VERSION 5.8 ;
BUSBITCHARS "[]" ;
DIVIDERCHAR "/" ;
UNITS
    DATABASE MICRONS 1000 ;
END UNITS

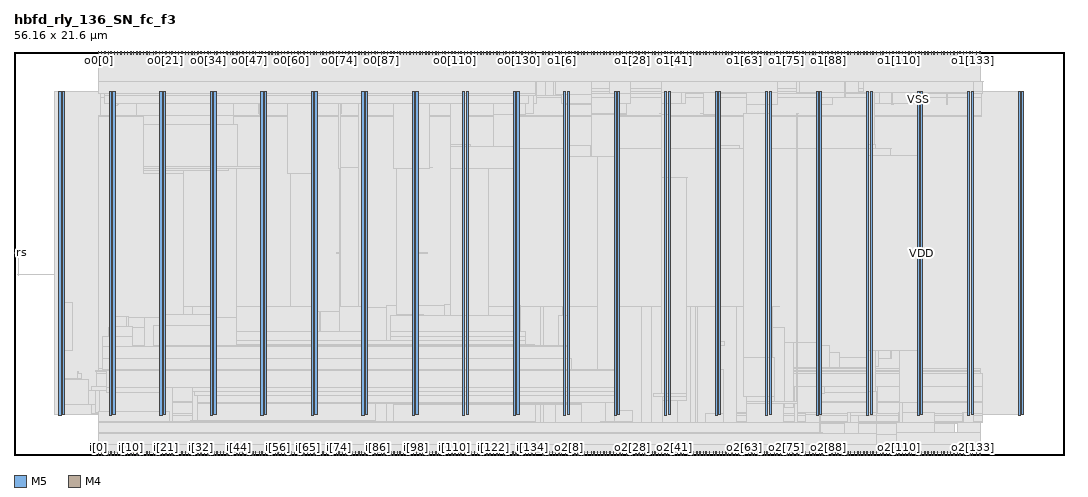
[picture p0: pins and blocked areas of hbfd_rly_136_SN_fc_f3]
MACRO hbfd_rly_136_SN_fc_f3
  FOREIGN hbfd_rly_136_SN_fc_f3 0 0 ;
  CLASS BLOCK ;
  SIZE 56.16 BY 21.6 ;
  PIN clk_in
    DIRECTION INPUT ;
    USE SIGNAL ;
    PORT
      LAYER M5 ;
        RECT  16.176 0 16.2 0.192 ;
    END
  END clk_in
  PIN clk_out0
    DIRECTION OUTPUT ;
    USE SIGNAL ;
    PORT
      LAYER M5 ;
        RECT  16.176 21.408 16.2 21.6 ;
    END
  END clk_out0
  PIN clk_out1
    DIRECTION OUTPUT ;
    USE SIGNAL ;
    PORT
      LAYER M5 ;
        RECT  39.936 21.408 39.96 21.6 ;
    END
  END clk_out1
  PIN clk_out2
    DIRECTION OUTPUT ;
    USE SIGNAL ;
    PORT
      LAYER M5 ;
        RECT  39.936 0 39.96 0.192 ;
    END
  END clk_out2
  PIN i[0]
    DIRECTION INPUT ;
    USE SIGNAL ;
    PORT
      LAYER M5 ;
        RECT  4.512 0 4.536 0.192 ;
    END
  END i[0]
  PIN i[100]
    DIRECTION INPUT ;
    USE SIGNAL ;
    PORT
      LAYER M5 ;
        RECT  21.84 0 21.864 0.192 ;
    END
  END i[100]
  PIN i[101]
    DIRECTION INPUT ;
    USE SIGNAL ;
    PORT
      LAYER M5 ;
        RECT  22.032 0 22.056 0.192 ;
    END
  END i[101]
  PIN i[102]
    DIRECTION INPUT ;
    USE SIGNAL ;
    PORT
      LAYER M5 ;
        RECT  22.176 0 22.2 0.192 ;
    END
  END i[102]
  PIN i[103]
    DIRECTION INPUT ;
    USE SIGNAL ;
    PORT
      LAYER M5 ;
        RECT  22.368 0 22.392 0.192 ;
    END
  END i[103]
  PIN i[104]
    DIRECTION INPUT ;
    USE SIGNAL ;
    PORT
      LAYER M5 ;
        RECT  22.56 0 22.584 0.192 ;
    END
  END i[104]
  PIN i[105]
    DIRECTION INPUT ;
    USE SIGNAL ;
    PORT
      LAYER M5 ;
        RECT  22.704 0 22.728 0.192 ;
    END
  END i[105]
  PIN i[106]
    DIRECTION INPUT ;
    USE SIGNAL ;
    PORT
      LAYER M5 ;
        RECT  22.896 0 22.92 0.192 ;
    END
  END i[106]
  PIN i[107]
    DIRECTION INPUT ;
    USE SIGNAL ;
    PORT
      LAYER M5 ;
        RECT  23.04 0 23.064 0.192 ;
    END
  END i[107]
  PIN i[108]
    DIRECTION INPUT ;
    USE SIGNAL ;
    PORT
      LAYER M5 ;
        RECT  23.232 0 23.256 0.192 ;
    END
  END i[108]
  PIN i[109]
    DIRECTION INPUT ;
    USE SIGNAL ;
    PORT
      LAYER M5 ;
        RECT  23.424 0 23.448 0.192 ;
    END
  END i[109]
  PIN i[10]
    DIRECTION INPUT ;
    USE SIGNAL ;
    PORT
      LAYER M5 ;
        RECT  6.24 0 6.264 0.192 ;
    END
  END i[10]
  PIN i[110]
    DIRECTION INPUT ;
    USE SIGNAL ;
    PORT
      LAYER M5 ;
        RECT  23.568 0 23.592 0.192 ;
    END
  END i[110]
  PIN i[111]
    DIRECTION INPUT ;
    USE SIGNAL ;
    PORT
      LAYER M5 ;
        RECT  23.76 0 23.784 0.192 ;
    END
  END i[111]
  PIN i[112]
    DIRECTION INPUT ;
    USE SIGNAL ;
    PORT
      LAYER M5 ;
        RECT  23.904 0 23.928 0.192 ;
    END
  END i[112]
  PIN i[113]
    DIRECTION INPUT ;
    USE SIGNAL ;
    PORT
      LAYER M5 ;
        RECT  24.096 0 24.12 0.192 ;
    END
  END i[113]
  PIN i[114]
    DIRECTION INPUT ;
    USE SIGNAL ;
    PORT
      LAYER M5 ;
        RECT  24.24 0 24.264 0.192 ;
    END
  END i[114]
  PIN i[115]
    DIRECTION INPUT ;
    USE SIGNAL ;
    PORT
      LAYER M5 ;
        RECT  24.432 0 24.456 0.192 ;
    END
  END i[115]
  PIN i[116]
    DIRECTION INPUT ;
    USE SIGNAL ;
    PORT
      LAYER M5 ;
        RECT  24.624 0 24.648 0.192 ;
    END
  END i[116]
  PIN i[117]
    DIRECTION INPUT ;
    USE SIGNAL ;
    PORT
      LAYER M5 ;
        RECT  24.768 0 24.792 0.192 ;
    END
  END i[117]
  PIN i[118]
    DIRECTION INPUT ;
    USE SIGNAL ;
    PORT
      LAYER M5 ;
        RECT  24.96 0 24.984 0.192 ;
    END
  END i[118]
  PIN i[119]
    DIRECTION INPUT ;
    USE SIGNAL ;
    PORT
      LAYER M5 ;
        RECT  25.104 0 25.128 0.192 ;
    END
  END i[119]
  PIN i[11]
    DIRECTION INPUT ;
    USE SIGNAL ;
    PORT
      LAYER M5 ;
        RECT  6.384 0 6.408 0.192 ;
    END
  END i[11]
  PIN i[120]
    DIRECTION INPUT ;
    USE SIGNAL ;
    PORT
      LAYER M5 ;
        RECT  25.296 0 25.32 0.192 ;
    END
  END i[120]
  PIN i[121]
    DIRECTION INPUT ;
    USE SIGNAL ;
    PORT
      LAYER M5 ;
        RECT  25.44 0 25.464 0.192 ;
    END
  END i[121]
  PIN i[122]
    DIRECTION INPUT ;
    USE SIGNAL ;
    PORT
      LAYER M5 ;
        RECT  25.632 0 25.656 0.192 ;
    END
  END i[122]
  PIN i[123]
    DIRECTION INPUT ;
    USE SIGNAL ;
    PORT
      LAYER M5 ;
        RECT  25.824 0 25.848 0.192 ;
    END
  END i[123]
  PIN i[124]
    DIRECTION INPUT ;
    USE SIGNAL ;
    PORT
      LAYER M5 ;
        RECT  25.968 0 25.992 0.192 ;
    END
  END i[124]
  PIN i[125]
    DIRECTION INPUT ;
    USE SIGNAL ;
    PORT
      LAYER M5 ;
        RECT  26.16 0 26.184 0.192 ;
    END
  END i[125]
  PIN i[126]
    DIRECTION INPUT ;
    USE SIGNAL ;
    PORT
      LAYER M5 ;
        RECT  26.304 0 26.328 0.192 ;
    END
  END i[126]
  PIN i[127]
    DIRECTION INPUT ;
    USE SIGNAL ;
    PORT
      LAYER M5 ;
        RECT  26.496 0 26.52 0.192 ;
    END
  END i[127]
  PIN i[128]
    DIRECTION INPUT ;
    USE SIGNAL ;
    PORT
      LAYER M5 ;
        RECT  26.688 0 26.712 0.192 ;
    END
  END i[128]
  PIN i[129]
    DIRECTION INPUT ;
    USE SIGNAL ;
    PORT
      LAYER M5 ;
        RECT  26.832 0 26.856 0.192 ;
    END
  END i[129]
  PIN i[12]
    DIRECTION INPUT ;
    USE SIGNAL ;
    PORT
      LAYER M5 ;
        RECT  6.576 0 6.6 0.192 ;
    END
  END i[12]
  PIN i[130]
    DIRECTION INPUT ;
    USE SIGNAL ;
    PORT
      LAYER M5 ;
        RECT  27.024 0 27.048 0.192 ;
    END
  END i[130]
  PIN i[131]
    DIRECTION INPUT ;
    USE SIGNAL ;
    PORT
      LAYER M5 ;
        RECT  27.168 0 27.192 0.192 ;
    END
  END i[131]
  PIN i[132]
    DIRECTION INPUT ;
    USE SIGNAL ;
    PORT
      LAYER M5 ;
        RECT  27.36 0 27.384 0.192 ;
    END
  END i[132]
  PIN i[133]
    DIRECTION INPUT ;
    USE SIGNAL ;
    PORT
      LAYER M5 ;
        RECT  27.504 0 27.528 0.192 ;
    END
  END i[133]
  PIN i[134]
    DIRECTION INPUT ;
    USE SIGNAL ;
    PORT
      LAYER M5 ;
        RECT  27.696 0 27.72 0.192 ;
    END
  END i[134]
  PIN i[135]
    DIRECTION INPUT ;
    USE SIGNAL ;
    PORT
      LAYER M5 ;
        RECT  27.888 0 27.912 0.192 ;
    END
  END i[135]
  PIN i[13]
    DIRECTION INPUT ;
    USE SIGNAL ;
    PORT
      LAYER M5 ;
        RECT  6.72 0 6.744 0.192 ;
    END
  END i[13]
  PIN i[14]
    DIRECTION INPUT ;
    USE SIGNAL ;
    PORT
      LAYER M5 ;
        RECT  6.912 0 6.936 0.192 ;
    END
  END i[14]
  PIN i[15]
    DIRECTION INPUT ;
    USE SIGNAL ;
    PORT
      LAYER M5 ;
        RECT  7.104 0 7.128 0.192 ;
    END
  END i[15]
  PIN i[16]
    DIRECTION INPUT ;
    USE SIGNAL ;
    PORT
      LAYER M5 ;
        RECT  7.248 0 7.272 0.192 ;
    END
  END i[16]
  PIN i[17]
    DIRECTION INPUT ;
    USE SIGNAL ;
    PORT
      LAYER M5 ;
        RECT  7.44 0 7.464 0.192 ;
    END
  END i[17]
  PIN i[18]
    DIRECTION INPUT ;
    USE SIGNAL ;
    PORT
      LAYER M5 ;
        RECT  7.584 0 7.608 0.192 ;
    END
  END i[18]
  PIN i[19]
    DIRECTION INPUT ;
    USE SIGNAL ;
    PORT
      LAYER M5 ;
        RECT  7.776 0 7.8 0.192 ;
    END
  END i[19]
  PIN i[1]
    DIRECTION INPUT ;
    USE SIGNAL ;
    PORT
      LAYER M5 ;
        RECT  4.656 0 4.68 0.192 ;
    END
  END i[1]
  PIN i[20]
    DIRECTION INPUT ;
    USE SIGNAL ;
    PORT
      LAYER M5 ;
        RECT  7.92 0 7.944 0.192 ;
    END
  END i[20]
  PIN i[21]
    DIRECTION INPUT ;
    USE SIGNAL ;
    PORT
      LAYER M5 ;
        RECT  8.112 0 8.136 0.192 ;
    END
  END i[21]
  PIN i[22]
    DIRECTION INPUT ;
    USE SIGNAL ;
    PORT
      LAYER M5 ;
        RECT  8.304 0 8.328 0.192 ;
    END
  END i[22]
  PIN i[23]
    DIRECTION INPUT ;
    USE SIGNAL ;
    PORT
      LAYER M5 ;
        RECT  8.448 0 8.472 0.192 ;
    END
  END i[23]
  PIN i[24]
    DIRECTION INPUT ;
    USE SIGNAL ;
    PORT
      LAYER M5 ;
        RECT  8.64 0 8.664 0.192 ;
    END
  END i[24]
  PIN i[25]
    DIRECTION INPUT ;
    USE SIGNAL ;
    PORT
      LAYER M5 ;
        RECT  8.784 0 8.808 0.192 ;
    END
  END i[25]
  PIN i[26]
    DIRECTION INPUT ;
    USE SIGNAL ;
    PORT
      LAYER M5 ;
        RECT  8.976 0 9 0.192 ;
    END
  END i[26]
  PIN i[27]
    DIRECTION INPUT ;
    USE SIGNAL ;
    PORT
      LAYER M5 ;
        RECT  9.168 0 9.192 0.192 ;
    END
  END i[27]
  PIN i[28]
    DIRECTION INPUT ;
    USE SIGNAL ;
    PORT
      LAYER M5 ;
        RECT  9.312 0 9.336 0.192 ;
    END
  END i[28]
  PIN i[29]
    DIRECTION INPUT ;
    USE SIGNAL ;
    PORT
      LAYER M5 ;
        RECT  9.504 0 9.528 0.192 ;
    END
  END i[29]
  PIN i[2]
    DIRECTION INPUT ;
    USE SIGNAL ;
    PORT
      LAYER M5 ;
        RECT  4.848 0 4.872 0.192 ;
    END
  END i[2]
  PIN i[30]
    DIRECTION INPUT ;
    USE SIGNAL ;
    PORT
      LAYER M5 ;
        RECT  9.648 0 9.672 0.192 ;
    END
  END i[30]
  PIN i[31]
    DIRECTION INPUT ;
    USE SIGNAL ;
    PORT
      LAYER M5 ;
        RECT  9.84 0 9.864 0.192 ;
    END
  END i[31]
  PIN i[32]
    DIRECTION INPUT ;
    USE SIGNAL ;
    PORT
      LAYER M5 ;
        RECT  9.984 0 10.008 0.192 ;
    END
  END i[32]
  PIN i[33]
    DIRECTION INPUT ;
    USE SIGNAL ;
    PORT
      LAYER M5 ;
        RECT  10.176 0 10.2 0.192 ;
    END
  END i[33]
  PIN i[34]
    DIRECTION INPUT ;
    USE SIGNAL ;
    PORT
      LAYER M5 ;
        RECT  10.368 0 10.392 0.192 ;
    END
  END i[34]
  PIN i[35]
    DIRECTION INPUT ;
    USE SIGNAL ;
    PORT
      LAYER M5 ;
        RECT  10.512 0 10.536 0.192 ;
    END
  END i[35]
  PIN i[36]
    DIRECTION INPUT ;
    USE SIGNAL ;
    PORT
      LAYER M5 ;
        RECT  10.704 0 10.728 0.192 ;
    END
  END i[36]
  PIN i[37]
    DIRECTION INPUT ;
    USE SIGNAL ;
    PORT
      LAYER M5 ;
        RECT  10.848 0 10.872 0.192 ;
    END
  END i[37]
  PIN i[38]
    DIRECTION INPUT ;
    USE SIGNAL ;
    PORT
      LAYER M5 ;
        RECT  11.04 0 11.064 0.192 ;
    END
  END i[38]
  PIN i[39]
    DIRECTION INPUT ;
    USE SIGNAL ;
    PORT
      LAYER M5 ;
        RECT  11.184 0 11.208 0.192 ;
    END
  END i[39]
  PIN i[3]
    DIRECTION INPUT ;
    USE SIGNAL ;
    PORT
      LAYER M5 ;
        RECT  5.04 0 5.064 0.192 ;
    END
  END i[3]
  PIN i[40]
    DIRECTION INPUT ;
    USE SIGNAL ;
    PORT
      LAYER M5 ;
        RECT  11.376 0 11.4 0.192 ;
    END
  END i[40]
  PIN i[41]
    DIRECTION INPUT ;
    USE SIGNAL ;
    PORT
      LAYER M5 ;
        RECT  11.568 0 11.592 0.192 ;
    END
  END i[41]
  PIN i[42]
    DIRECTION INPUT ;
    USE SIGNAL ;
    PORT
      LAYER M5 ;
        RECT  11.712 0 11.736 0.192 ;
    END
  END i[42]
  PIN i[43]
    DIRECTION INPUT ;
    USE SIGNAL ;
    PORT
      LAYER M5 ;
        RECT  11.904 0 11.928 0.192 ;
    END
  END i[43]
  PIN i[44]
    DIRECTION INPUT ;
    USE SIGNAL ;
    PORT
      LAYER M5 ;
        RECT  12.048 0 12.072 0.192 ;
    END
  END i[44]
  PIN i[45]
    DIRECTION INPUT ;
    USE SIGNAL ;
    PORT
      LAYER M5 ;
        RECT  12.24 0 12.264 0.192 ;
    END
  END i[45]
  PIN i[46]
    DIRECTION INPUT ;
    USE SIGNAL ;
    PORT
      LAYER M5 ;
        RECT  12.432 0 12.456 0.192 ;
    END
  END i[46]
  PIN i[47]
    DIRECTION INPUT ;
    USE SIGNAL ;
    PORT
      LAYER M5 ;
        RECT  12.576 0 12.6 0.192 ;
    END
  END i[47]
  PIN i[48]
    DIRECTION INPUT ;
    USE SIGNAL ;
    PORT
      LAYER M5 ;
        RECT  12.768 0 12.792 0.192 ;
    END
  END i[48]
  PIN i[49]
    DIRECTION INPUT ;
    USE SIGNAL ;
    PORT
      LAYER M5 ;
        RECT  12.912 0 12.936 0.192 ;
    END
  END i[49]
  PIN i[4]
    DIRECTION INPUT ;
    USE SIGNAL ;
    PORT
      LAYER M5 ;
        RECT  5.184 0 5.208 0.192 ;
    END
  END i[4]
  PIN i[50]
    DIRECTION INPUT ;
    USE SIGNAL ;
    PORT
      LAYER M5 ;
        RECT  13.104 0 13.128 0.192 ;
    END
  END i[50]
  PIN i[51]
    DIRECTION INPUT ;
    USE SIGNAL ;
    PORT
      LAYER M5 ;
        RECT  13.248 0 13.272 0.192 ;
    END
  END i[51]
  PIN i[52]
    DIRECTION INPUT ;
    USE SIGNAL ;
    PORT
      LAYER M5 ;
        RECT  13.44 0 13.464 0.192 ;
    END
  END i[52]
  PIN i[53]
    DIRECTION INPUT ;
    USE SIGNAL ;
    PORT
      LAYER M5 ;
        RECT  13.632 0 13.656 0.192 ;
    END
  END i[53]
  PIN i[54]
    DIRECTION INPUT ;
    USE SIGNAL ;
    PORT
      LAYER M5 ;
        RECT  13.776 0 13.8 0.192 ;
    END
  END i[54]
  PIN i[55]
    DIRECTION INPUT ;
    USE SIGNAL ;
    PORT
      LAYER M5 ;
        RECT  13.968 0 13.992 0.192 ;
    END
  END i[55]
  PIN i[56]
    DIRECTION INPUT ;
    USE SIGNAL ;
    PORT
      LAYER M5 ;
        RECT  14.112 0 14.136 0.192 ;
    END
  END i[56]
  PIN i[57]
    DIRECTION INPUT ;
    USE SIGNAL ;
    PORT
      LAYER M5 ;
        RECT  14.304 0 14.328 0.192 ;
    END
  END i[57]
  PIN i[58]
    DIRECTION INPUT ;
    USE SIGNAL ;
    PORT
      LAYER M5 ;
        RECT  14.448 0 14.472 0.192 ;
    END
  END i[58]
  PIN i[59]
    DIRECTION INPUT ;
    USE SIGNAL ;
    PORT
      LAYER M5 ;
        RECT  14.64 0 14.664 0.192 ;
    END
  END i[59]
  PIN i[5]
    DIRECTION INPUT ;
    USE SIGNAL ;
    PORT
      LAYER M5 ;
        RECT  5.376 0 5.4 0.192 ;
    END
  END i[5]
  PIN i[60]
    DIRECTION INPUT ;
    USE SIGNAL ;
    PORT
      LAYER M5 ;
        RECT  14.832 0 14.856 0.192 ;
    END
  END i[60]
  PIN i[61]
    DIRECTION INPUT ;
    USE SIGNAL ;
    PORT
      LAYER M5 ;
        RECT  14.976 0 15 0.192 ;
    END
  END i[61]
  PIN i[62]
    DIRECTION INPUT ;
    USE SIGNAL ;
    PORT
      LAYER M5 ;
        RECT  15.168 0 15.192 0.192 ;
    END
  END i[62]
  PIN i[63]
    DIRECTION INPUT ;
    USE SIGNAL ;
    PORT
      LAYER M5 ;
        RECT  15.312 0 15.336 0.192 ;
    END
  END i[63]
  PIN i[64]
    DIRECTION INPUT ;
    USE SIGNAL ;
    PORT
      LAYER M5 ;
        RECT  15.504 0 15.528 0.192 ;
    END
  END i[64]
  PIN i[65]
    DIRECTION INPUT ;
    USE SIGNAL ;
    PORT
      LAYER M5 ;
        RECT  15.696 0 15.72 0.192 ;
    END
  END i[65]
  PIN i[66]
    DIRECTION INPUT ;
    USE SIGNAL ;
    PORT
      LAYER M5 ;
        RECT  15.84 0 15.864 0.192 ;
    END
  END i[66]
  PIN i[67]
    DIRECTION INPUT ;
    USE SIGNAL ;
    PORT
      LAYER M5 ;
        RECT  16.032 0 16.056 0.192 ;
    END
  END i[67]
  PIN i[68]
    DIRECTION INPUT ;
    USE SIGNAL ;
    PORT
      LAYER M5 ;
        RECT  16.368 0 16.392 0.192 ;
    END
  END i[68]
  PIN i[69]
    DIRECTION INPUT ;
    USE SIGNAL ;
    PORT
      LAYER M5 ;
        RECT  16.512 0 16.536 0.192 ;
    END
  END i[69]
  PIN i[6]
    DIRECTION INPUT ;
    USE SIGNAL ;
    PORT
      LAYER M5 ;
        RECT  5.52 0 5.544 0.192 ;
    END
  END i[6]
  PIN i[70]
    DIRECTION INPUT ;
    USE SIGNAL ;
    PORT
      LAYER M5 ;
        RECT  16.704 0 16.728 0.192 ;
    END
  END i[70]
  PIN i[71]
    DIRECTION INPUT ;
    USE SIGNAL ;
    PORT
      LAYER M5 ;
        RECT  16.896 0 16.92 0.192 ;
    END
  END i[71]
  PIN i[72]
    DIRECTION INPUT ;
    USE SIGNAL ;
    PORT
      LAYER M5 ;
        RECT  17.04 0 17.064 0.192 ;
    END
  END i[72]
  PIN i[73]
    DIRECTION INPUT ;
    USE SIGNAL ;
    PORT
      LAYER M5 ;
        RECT  17.232 0 17.256 0.192 ;
    END
  END i[73]
  PIN i[74]
    DIRECTION INPUT ;
    USE SIGNAL ;
    PORT
      LAYER M5 ;
        RECT  17.376 0 17.4 0.192 ;
    END
  END i[74]
  PIN i[75]
    DIRECTION INPUT ;
    USE SIGNAL ;
    PORT
      LAYER M5 ;
        RECT  17.568 0 17.592 0.192 ;
    END
  END i[75]
  PIN i[76]
    DIRECTION INPUT ;
    USE SIGNAL ;
    PORT
      LAYER M5 ;
        RECT  17.712 0 17.736 0.192 ;
    END
  END i[76]
  PIN i[77]
    DIRECTION INPUT ;
    USE SIGNAL ;
    PORT
      LAYER M5 ;
        RECT  17.904 0 17.928 0.192 ;
    END
  END i[77]
  PIN i[78]
    DIRECTION INPUT ;
    USE SIGNAL ;
    PORT
      LAYER M5 ;
        RECT  18.096 0 18.12 0.192 ;
    END
  END i[78]
  PIN i[79]
    DIRECTION INPUT ;
    USE SIGNAL ;
    PORT
      LAYER M5 ;
        RECT  18.24 0 18.264 0.192 ;
    END
  END i[79]
  PIN i[7]
    DIRECTION INPUT ;
    USE SIGNAL ;
    PORT
      LAYER M5 ;
        RECT  5.712 0 5.736 0.192 ;
    END
  END i[7]
  PIN i[80]
    DIRECTION INPUT ;
    USE SIGNAL ;
    PORT
      LAYER M5 ;
        RECT  18.432 0 18.456 0.192 ;
    END
  END i[80]
  PIN i[81]
    DIRECTION INPUT ;
    USE SIGNAL ;
    PORT
      LAYER M5 ;
        RECT  18.576 0 18.6 0.192 ;
    END
  END i[81]
  PIN i[82]
    DIRECTION INPUT ;
    USE SIGNAL ;
    PORT
      LAYER M5 ;
        RECT  18.768 0 18.792 0.192 ;
    END
  END i[82]
  PIN i[83]
    DIRECTION INPUT ;
    USE SIGNAL ;
    PORT
      LAYER M5 ;
        RECT  18.96 0 18.984 0.192 ;
    END
  END i[83]
  PIN i[84]
    DIRECTION INPUT ;
    USE SIGNAL ;
    PORT
      LAYER M5 ;
        RECT  19.104 0 19.128 0.192 ;
    END
  END i[84]
  PIN i[85]
    DIRECTION INPUT ;
    USE SIGNAL ;
    PORT
      LAYER M5 ;
        RECT  19.296 0 19.32 0.192 ;
    END
  END i[85]
  PIN i[86]
    DIRECTION INPUT ;
    USE SIGNAL ;
    PORT
      LAYER M5 ;
        RECT  19.44 0 19.464 0.192 ;
    END
  END i[86]
  PIN i[87]
    DIRECTION INPUT ;
    USE SIGNAL ;
    PORT
      LAYER M5 ;
        RECT  19.632 0 19.656 0.192 ;
    END
  END i[87]
  PIN i[88]
    DIRECTION INPUT ;
    USE SIGNAL ;
    PORT
      LAYER M5 ;
        RECT  19.776 0 19.8 0.192 ;
    END
  END i[88]
  PIN i[89]
    DIRECTION INPUT ;
    USE SIGNAL ;
    PORT
      LAYER M5 ;
        RECT  19.968 0 19.992 0.192 ;
    END
  END i[89]
  PIN i[8]
    DIRECTION INPUT ;
    USE SIGNAL ;
    PORT
      LAYER M5 ;
        RECT  5.904 0 5.928 0.192 ;
    END
  END i[8]
  PIN i[90]
    DIRECTION INPUT ;
    USE SIGNAL ;
    PORT
      LAYER M5 ;
        RECT  20.16 0 20.184 0.192 ;
    END
  END i[90]
  PIN i[91]
    DIRECTION INPUT ;
    USE SIGNAL ;
    PORT
      LAYER M5 ;
        RECT  20.304 0 20.328 0.192 ;
    END
  END i[91]
  PIN i[92]
    DIRECTION INPUT ;
    USE SIGNAL ;
    PORT
      LAYER M5 ;
        RECT  20.496 0 20.52 0.192 ;
    END
  END i[92]
  PIN i[93]
    DIRECTION INPUT ;
    USE SIGNAL ;
    PORT
      LAYER M5 ;
        RECT  20.64 0 20.664 0.192 ;
    END
  END i[93]
  PIN i[94]
    DIRECTION INPUT ;
    USE SIGNAL ;
    PORT
      LAYER M5 ;
        RECT  20.832 0 20.856 0.192 ;
    END
  END i[94]
  PIN i[95]
    DIRECTION INPUT ;
    USE SIGNAL ;
    PORT
      LAYER M5 ;
        RECT  20.976 0 21 0.192 ;
    END
  END i[95]
  PIN i[96]
    DIRECTION INPUT ;
    USE SIGNAL ;
    PORT
      LAYER M5 ;
        RECT  21.168 0 21.192 0.192 ;
    END
  END i[96]
  PIN i[97]
    DIRECTION INPUT ;
    USE SIGNAL ;
    PORT
      LAYER M5 ;
        RECT  21.36 0 21.384 0.192 ;
    END
  END i[97]
  PIN i[98]
    DIRECTION INPUT ;
    USE SIGNAL ;
    PORT
      LAYER M5 ;
        RECT  21.504 0 21.528 0.192 ;
    END
  END i[98]
  PIN i[99]
    DIRECTION INPUT ;
    USE SIGNAL ;
    PORT
      LAYER M5 ;
        RECT  21.696 0 21.72 0.192 ;
    END
  END i[99]
  PIN i[9]
    DIRECTION INPUT ;
    USE SIGNAL ;
    PORT
      LAYER M5 ;
        RECT  6.048 0 6.072 0.192 ;
    END
  END i[9]
  PIN o0[0]
    DIRECTION OUTPUT ;
    USE SIGNAL ;
    PORT
      LAYER M5 ;
        RECT  4.512 21.408 4.536 21.6 ;
    END
  END o0[0]
  PIN o0[100]
    DIRECTION OUTPUT ;
    USE SIGNAL ;
    PORT
      LAYER M5 ;
        RECT  21.84 21.408 21.864 21.6 ;
    END
  END o0[100]
  PIN o0[101]
    DIRECTION OUTPUT ;
    USE SIGNAL ;
    PORT
      LAYER M5 ;
        RECT  22.032 21.408 22.056 21.6 ;
    END
  END o0[101]
  PIN o0[102]
    DIRECTION OUTPUT ;
    USE SIGNAL ;
    PORT
      LAYER M5 ;
        RECT  22.176 21.408 22.2 21.6 ;
    END
  END o0[102]
  PIN o0[103]
    DIRECTION OUTPUT ;
    USE SIGNAL ;
    PORT
      LAYER M5 ;
        RECT  22.368 21.408 22.392 21.6 ;
    END
  END o0[103]
  PIN o0[104]
    DIRECTION OUTPUT ;
    USE SIGNAL ;
    PORT
      LAYER M5 ;
        RECT  22.56 21.408 22.584 21.6 ;
    END
  END o0[104]
  PIN o0[105]
    DIRECTION OUTPUT ;
    USE SIGNAL ;
    PORT
      LAYER M5 ;
        RECT  22.704 21.408 22.728 21.6 ;
    END
  END o0[105]
  PIN o0[106]
    DIRECTION OUTPUT ;
    USE SIGNAL ;
    PORT
      LAYER M5 ;
        RECT  22.896 21.408 22.92 21.6 ;
    END
  END o0[106]
  PIN o0[107]
    DIRECTION OUTPUT ;
    USE SIGNAL ;
    PORT
      LAYER M5 ;
        RECT  23.04 21.408 23.064 21.6 ;
    END
  END o0[107]
  PIN o0[108]
    DIRECTION OUTPUT ;
    USE SIGNAL ;
    PORT
      LAYER M5 ;
        RECT  23.232 21.408 23.256 21.6 ;
    END
  END o0[108]
  PIN o0[109]
    DIRECTION OUTPUT ;
    USE SIGNAL ;
    PORT
      LAYER M5 ;
        RECT  23.424 21.408 23.448 21.6 ;
    END
  END o0[109]
  PIN o0[10]
    DIRECTION OUTPUT ;
    USE SIGNAL ;
    PORT
      LAYER M5 ;
        RECT  6.24 21.408 6.264 21.6 ;
    END
  END o0[10]
  PIN o0[110]
    DIRECTION OUTPUT ;
    USE SIGNAL ;
    PORT
      LAYER M5 ;
        RECT  23.568 21.408 23.592 21.6 ;
    END
  END o0[110]
  PIN o0[111]
    DIRECTION OUTPUT ;
    USE SIGNAL ;
    PORT
      LAYER M5 ;
        RECT  23.76 21.408 23.784 21.6 ;
    END
  END o0[111]
  PIN o0[112]
    DIRECTION OUTPUT ;
    USE SIGNAL ;
    PORT
      LAYER M5 ;
        RECT  23.904 21.408 23.928 21.6 ;
    END
  END o0[112]
  PIN o0[113]
    DIRECTION OUTPUT ;
    USE SIGNAL ;
    PORT
      LAYER M5 ;
        RECT  24.096 21.408 24.12 21.6 ;
    END
  END o0[113]
  PIN o0[114]
    DIRECTION OUTPUT ;
    USE SIGNAL ;
    PORT
      LAYER M5 ;
        RECT  24.24 21.408 24.264 21.6 ;
    END
  END o0[114]
  PIN o0[115]
    DIRECTION OUTPUT ;
    USE SIGNAL ;
    PORT
      LAYER M5 ;
        RECT  24.432 21.408 24.456 21.6 ;
    END
  END o0[115]
  PIN o0[116]
    DIRECTION OUTPUT ;
    USE SIGNAL ;
    PORT
      LAYER M5 ;
        RECT  24.624 21.408 24.648 21.6 ;
    END
  END o0[116]
  PIN o0[117]
    DIRECTION OUTPUT ;
    USE SIGNAL ;
    PORT
      LAYER M5 ;
        RECT  24.768 21.408 24.792 21.6 ;
    END
  END o0[117]
  PIN o0[118]
    DIRECTION OUTPUT ;
    USE SIGNAL ;
    PORT
      LAYER M5 ;
        RECT  24.96 21.408 24.984 21.6 ;
    END
  END o0[118]
  PIN o0[119]
    DIRECTION OUTPUT ;
    USE SIGNAL ;
    PORT
      LAYER M5 ;
        RECT  25.104 21.408 25.128 21.6 ;
    END
  END o0[119]
  PIN o0[11]
    DIRECTION OUTPUT ;
    USE SIGNAL ;
    PORT
      LAYER M5 ;
        RECT  6.384 21.408 6.408 21.6 ;
    END
  END o0[11]
  PIN o0[120]
    DIRECTION OUTPUT ;
    USE SIGNAL ;
    PORT
      LAYER M5 ;
        RECT  25.296 21.408 25.32 21.6 ;
    END
  END o0[120]
  PIN o0[121]
    DIRECTION OUTPUT ;
    USE SIGNAL ;
    PORT
      LAYER M5 ;
        RECT  25.44 21.408 25.464 21.6 ;
    END
  END o0[121]
  PIN o0[122]
    DIRECTION OUTPUT ;
    USE SIGNAL ;
    PORT
      LAYER M5 ;
        RECT  25.632 21.408 25.656 21.6 ;
    END
  END o0[122]
  PIN o0[123]
    DIRECTION OUTPUT ;
    USE SIGNAL ;
    PORT
      LAYER M5 ;
        RECT  25.824 21.408 25.848 21.6 ;
    END
  END o0[123]
  PIN o0[124]
    DIRECTION OUTPUT ;
    USE SIGNAL ;
    PORT
      LAYER M5 ;
        RECT  25.968 21.408 25.992 21.6 ;
    END
  END o0[124]
  PIN o0[125]
    DIRECTION OUTPUT ;
    USE SIGNAL ;
    PORT
      LAYER M5 ;
        RECT  26.16 21.408 26.184 21.6 ;
    END
  END o0[125]
  PIN o0[126]
    DIRECTION OUTPUT ;
    USE SIGNAL ;
    PORT
      LAYER M5 ;
        RECT  26.304 21.408 26.328 21.6 ;
    END
  END o0[126]
  PIN o0[127]
    DIRECTION OUTPUT ;
    USE SIGNAL ;
    PORT
      LAYER M5 ;
        RECT  26.496 21.408 26.52 21.6 ;
    END
  END o0[127]
  PIN o0[128]
    DIRECTION OUTPUT ;
    USE SIGNAL ;
    PORT
      LAYER M5 ;
        RECT  26.688 21.408 26.712 21.6 ;
    END
  END o0[128]
  PIN o0[129]
    DIRECTION OUTPUT ;
    USE SIGNAL ;
    PORT
      LAYER M5 ;
        RECT  26.832 21.408 26.856 21.6 ;
    END
  END o0[129]
  PIN o0[12]
    DIRECTION OUTPUT ;
    USE SIGNAL ;
    PORT
      LAYER M5 ;
        RECT  6.576 21.408 6.6 21.6 ;
    END
  END o0[12]
  PIN o0[130]
    DIRECTION OUTPUT ;
    USE SIGNAL ;
    PORT
      LAYER M5 ;
        RECT  27.024 21.408 27.048 21.6 ;
    END
  END o0[130]
  PIN o0[131]
    DIRECTION OUTPUT ;
    USE SIGNAL ;
    PORT
      LAYER M5 ;
        RECT  27.168 21.408 27.192 21.6 ;
    END
  END o0[131]
  PIN o0[132]
    DIRECTION OUTPUT ;
    USE SIGNAL ;
    PORT
      LAYER M5 ;
        RECT  27.36 21.408 27.384 21.6 ;
    END
  END o0[132]
  PIN o0[133]
    DIRECTION OUTPUT ;
    USE SIGNAL ;
    PORT
      LAYER M5 ;
        RECT  27.504 21.408 27.528 21.6 ;
    END
  END o0[133]
  PIN o0[134]
    DIRECTION OUTPUT ;
    USE SIGNAL ;
    PORT
      LAYER M5 ;
        RECT  27.696 21.408 27.72 21.6 ;
    END
  END o0[134]
  PIN o0[135]
    DIRECTION OUTPUT ;
    USE SIGNAL ;
    PORT
      LAYER M5 ;
        RECT  27.888 21.408 27.912 21.6 ;
    END
  END o0[135]
  PIN o0[13]
    DIRECTION OUTPUT ;
    USE SIGNAL ;
    PORT
      LAYER M5 ;
        RECT  6.72 21.408 6.744 21.6 ;
    END
  END o0[13]
  PIN o0[14]
    DIRECTION OUTPUT ;
    USE SIGNAL ;
    PORT
      LAYER M5 ;
        RECT  6.912 21.408 6.936 21.6 ;
    END
  END o0[14]
  PIN o0[15]
    DIRECTION OUTPUT ;
    USE SIGNAL ;
    PORT
      LAYER M5 ;
        RECT  7.104 21.408 7.128 21.6 ;
    END
  END o0[15]
  PIN o0[16]
    DIRECTION OUTPUT ;
    USE SIGNAL ;
    PORT
      LAYER M5 ;
        RECT  7.248 21.408 7.272 21.6 ;
    END
  END o0[16]
  PIN o0[17]
    DIRECTION OUTPUT ;
    USE SIGNAL ;
    PORT
      LAYER M5 ;
        RECT  7.44 21.408 7.464 21.6 ;
    END
  END o0[17]
  PIN o0[18]
    DIRECTION OUTPUT ;
    USE SIGNAL ;
    PORT
      LAYER M5 ;
        RECT  7.584 21.408 7.608 21.6 ;
    END
  END o0[18]
  PIN o0[19]
    DIRECTION OUTPUT ;
    USE SIGNAL ;
    PORT
      LAYER M5 ;
        RECT  7.776 21.408 7.8 21.6 ;
    END
  END o0[19]
  PIN o0[1]
    DIRECTION OUTPUT ;
    USE SIGNAL ;
    PORT
      LAYER M5 ;
        RECT  4.656 21.408 4.68 21.6 ;
    END
  END o0[1]
  PIN o0[20]
    DIRECTION OUTPUT ;
    USE SIGNAL ;
    PORT
      LAYER M5 ;
        RECT  7.92 21.408 7.944 21.6 ;
    END
  END o0[20]
  PIN o0[21]
    DIRECTION OUTPUT ;
    USE SIGNAL ;
    PORT
      LAYER M5 ;
        RECT  8.112 21.408 8.136 21.6 ;
    END
  END o0[21]
  PIN o0[22]
    DIRECTION OUTPUT ;
    USE SIGNAL ;
    PORT
      LAYER M5 ;
        RECT  8.304 21.408 8.328 21.6 ;
    END
  END o0[22]
  PIN o0[23]
    DIRECTION OUTPUT ;
    USE SIGNAL ;
    PORT
      LAYER M5 ;
        RECT  8.448 21.408 8.472 21.6 ;
    END
  END o0[23]
  PIN o0[24]
    DIRECTION OUTPUT ;
    USE SIGNAL ;
    PORT
      LAYER M5 ;
        RECT  8.64 21.408 8.664 21.6 ;
    END
  END o0[24]
  PIN o0[25]
    DIRECTION OUTPUT ;
    USE SIGNAL ;
    PORT
      LAYER M5 ;
        RECT  8.784 21.408 8.808 21.6 ;
    END
  END o0[25]
  PIN o0[26]
    DIRECTION OUTPUT ;
    USE SIGNAL ;
    PORT
      LAYER M5 ;
        RECT  8.976 21.408 9 21.6 ;
    END
  END o0[26]
  PIN o0[27]
    DIRECTION OUTPUT ;
    USE SIGNAL ;
    PORT
      LAYER M5 ;
        RECT  9.168 21.408 9.192 21.6 ;
    END
  END o0[27]
  PIN o0[28]
    DIRECTION OUTPUT ;
    USE SIGNAL ;
    PORT
      LAYER M5 ;
        RECT  9.312 21.408 9.336 21.6 ;
    END
  END o0[28]
  PIN o0[29]
    DIRECTION OUTPUT ;
    USE SIGNAL ;
    PORT
      LAYER M5 ;
        RECT  9.504 21.408 9.528 21.6 ;
    END
  END o0[29]
  PIN o0[2]
    DIRECTION OUTPUT ;
    USE SIGNAL ;
    PORT
      LAYER M5 ;
        RECT  4.848 21.408 4.872 21.6 ;
    END
  END o0[2]
  PIN o0[30]
    DIRECTION OUTPUT ;
    USE SIGNAL ;
    PORT
      LAYER M5 ;
        RECT  9.648 21.408 9.672 21.6 ;
    END
  END o0[30]
  PIN o0[31]
    DIRECTION OUTPUT ;
    USE SIGNAL ;
    PORT
      LAYER M5 ;
        RECT  9.84 21.408 9.864 21.6 ;
    END
  END o0[31]
  PIN o0[32]
    DIRECTION OUTPUT ;
    USE SIGNAL ;
    PORT
      LAYER M5 ;
        RECT  9.984 21.408 10.008 21.6 ;
    END
  END o0[32]
  PIN o0[33]
    DIRECTION OUTPUT ;
    USE SIGNAL ;
    PORT
      LAYER M5 ;
        RECT  10.176 21.408 10.2 21.6 ;
    END
  END o0[33]
  PIN o0[34]
    DIRECTION OUTPUT ;
    USE SIGNAL ;
    PORT
      LAYER M5 ;
        RECT  10.368 21.408 10.392 21.6 ;
    END
  END o0[34]
  PIN o0[35]
    DIRECTION OUTPUT ;
    USE SIGNAL ;
    PORT
      LAYER M5 ;
        RECT  10.512 21.408 10.536 21.6 ;
    END
  END o0[35]
  PIN o0[36]
    DIRECTION OUTPUT ;
    USE SIGNAL ;
    PORT
      LAYER M5 ;
        RECT  10.704 21.408 10.728 21.6 ;
    END
  END o0[36]
  PIN o0[37]
    DIRECTION OUTPUT ;
    USE SIGNAL ;
    PORT
      LAYER M5 ;
        RECT  10.848 21.408 10.872 21.6 ;
    END
  END o0[37]
  PIN o0[38]
    DIRECTION OUTPUT ;
    USE SIGNAL ;
    PORT
      LAYER M5 ;
        RECT  11.04 21.408 11.064 21.6 ;
    END
  END o0[38]
  PIN o0[39]
    DIRECTION OUTPUT ;
    USE SIGNAL ;
    PORT
      LAYER M5 ;
        RECT  11.184 21.408 11.208 21.6 ;
    END
  END o0[39]
  PIN o0[3]
    DIRECTION OUTPUT ;
    USE SIGNAL ;
    PORT
      LAYER M5 ;
        RECT  5.04 21.408 5.064 21.6 ;
    END
  END o0[3]
  PIN o0[40]
    DIRECTION OUTPUT ;
    USE SIGNAL ;
    PORT
      LAYER M5 ;
        RECT  11.376 21.408 11.4 21.6 ;
    END
  END o0[40]
  PIN o0[41]
    DIRECTION OUTPUT ;
    USE SIGNAL ;
    PORT
      LAYER M5 ;
        RECT  11.568 21.408 11.592 21.6 ;
    END
  END o0[41]
  PIN o0[42]
    DIRECTION OUTPUT ;
    USE SIGNAL ;
    PORT
      LAYER M5 ;
        RECT  11.712 21.408 11.736 21.6 ;
    END
  END o0[42]
  PIN o0[43]
    DIRECTION OUTPUT ;
    USE SIGNAL ;
    PORT
      LAYER M5 ;
        RECT  11.904 21.408 11.928 21.6 ;
    END
  END o0[43]
  PIN o0[44]
    DIRECTION OUTPUT ;
    USE SIGNAL ;
    PORT
      LAYER M5 ;
        RECT  12.048 21.408 12.072 21.6 ;
    END
  END o0[44]
  PIN o0[45]
    DIRECTION OUTPUT ;
    USE SIGNAL ;
    PORT
      LAYER M5 ;
        RECT  12.24 21.408 12.264 21.6 ;
    END
  END o0[45]
  PIN o0[46]
    DIRECTION OUTPUT ;
    USE SIGNAL ;
    PORT
      LAYER M5 ;
        RECT  12.432 21.408 12.456 21.6 ;
    END
  END o0[46]
  PIN o0[47]
    DIRECTION OUTPUT ;
    USE SIGNAL ;
    PORT
      LAYER M5 ;
        RECT  12.576 21.408 12.6 21.6 ;
    END
  END o0[47]
  PIN o0[48]
    DIRECTION OUTPUT ;
    USE SIGNAL ;
    PORT
      LAYER M5 ;
        RECT  12.768 21.408 12.792 21.6 ;
    END
  END o0[48]
  PIN o0[49]
    DIRECTION OUTPUT ;
    USE SIGNAL ;
    PORT
      LAYER M5 ;
        RECT  12.912 21.408 12.936 21.6 ;
    END
  END o0[49]
  PIN o0[4]
    DIRECTION OUTPUT ;
    USE SIGNAL ;
    PORT
      LAYER M5 ;
        RECT  5.184 21.408 5.208 21.6 ;
    END
  END o0[4]
  PIN o0[50]
    DIRECTION OUTPUT ;
    USE SIGNAL ;
    PORT
      LAYER M5 ;
        RECT  13.104 21.408 13.128 21.6 ;
    END
  END o0[50]
  PIN o0[51]
    DIRECTION OUTPUT ;
    USE SIGNAL ;
    PORT
      LAYER M5 ;
        RECT  13.248 21.408 13.272 21.6 ;
    END
  END o0[51]
  PIN o0[52]
    DIRECTION OUTPUT ;
    USE SIGNAL ;
    PORT
      LAYER M5 ;
        RECT  13.44 21.408 13.464 21.6 ;
    END
  END o0[52]
  PIN o0[53]
    DIRECTION OUTPUT ;
    USE SIGNAL ;
    PORT
      LAYER M5 ;
        RECT  13.632 21.408 13.656 21.6 ;
    END
  END o0[53]
  PIN o0[54]
    DIRECTION OUTPUT ;
    USE SIGNAL ;
    PORT
      LAYER M5 ;
        RECT  13.776 21.408 13.8 21.6 ;
    END
  END o0[54]
  PIN o0[55]
    DIRECTION OUTPUT ;
    USE SIGNAL ;
    PORT
      LAYER M5 ;
        RECT  13.968 21.408 13.992 21.6 ;
    END
  END o0[55]
  PIN o0[56]
    DIRECTION OUTPUT ;
    USE SIGNAL ;
    PORT
      LAYER M5 ;
        RECT  14.112 21.408 14.136 21.6 ;
    END
  END o0[56]
  PIN o0[57]
    DIRECTION OUTPUT ;
    USE SIGNAL ;
    PORT
      LAYER M5 ;
        RECT  14.304 21.408 14.328 21.6 ;
    END
  END o0[57]
  PIN o0[58]
    DIRECTION OUTPUT ;
    USE SIGNAL ;
    PORT
      LAYER M5 ;
        RECT  14.448 21.408 14.472 21.6 ;
    END
  END o0[58]
  PIN o0[59]
    DIRECTION OUTPUT ;
    USE SIGNAL ;
    PORT
      LAYER M5 ;
        RECT  14.64 21.408 14.664 21.6 ;
    END
  END o0[59]
  PIN o0[5]
    DIRECTION OUTPUT ;
    USE SIGNAL ;
    PORT
      LAYER M5 ;
        RECT  5.376 21.408 5.4 21.6 ;
    END
  END o0[5]
  PIN o0[60]
    DIRECTION OUTPUT ;
    USE SIGNAL ;
    PORT
      LAYER M5 ;
        RECT  14.832 21.408 14.856 21.6 ;
    END
  END o0[60]
  PIN o0[61]
    DIRECTION OUTPUT ;
    USE SIGNAL ;
    PORT
      LAYER M5 ;
        RECT  14.976 21.408 15 21.6 ;
    END
  END o0[61]
  PIN o0[62]
    DIRECTION OUTPUT ;
    USE SIGNAL ;
    PORT
      LAYER M5 ;
        RECT  15.168 21.408 15.192 21.6 ;
    END
  END o0[62]
  PIN o0[63]
    DIRECTION OUTPUT ;
    USE SIGNAL ;
    PORT
      LAYER M5 ;
        RECT  15.312 21.408 15.336 21.6 ;
    END
  END o0[63]
  PIN o0[64]
    DIRECTION OUTPUT ;
    USE SIGNAL ;
    PORT
      LAYER M5 ;
        RECT  15.504 21.408 15.528 21.6 ;
    END
  END o0[64]
  PIN o0[65]
    DIRECTION OUTPUT ;
    USE SIGNAL ;
    PORT
      LAYER M5 ;
        RECT  15.696 21.408 15.72 21.6 ;
    END
  END o0[65]
  PIN o0[66]
    DIRECTION OUTPUT ;
    USE SIGNAL ;
    PORT
      LAYER M5 ;
        RECT  15.84 21.408 15.864 21.6 ;
    END
  END o0[66]
  PIN o0[67]
    DIRECTION OUTPUT ;
    USE SIGNAL ;
    PORT
      LAYER M5 ;
        RECT  16.032 21.408 16.056 21.6 ;
    END
  END o0[67]
  PIN o0[68]
    DIRECTION OUTPUT ;
    USE SIGNAL ;
    PORT
      LAYER M5 ;
        RECT  16.368 21.408 16.392 21.6 ;
    END
  END o0[68]
  PIN o0[69]
    DIRECTION OUTPUT ;
    USE SIGNAL ;
    PORT
      LAYER M5 ;
        RECT  16.512 21.408 16.536 21.6 ;
    END
  END o0[69]
  PIN o0[6]
    DIRECTION OUTPUT ;
    USE SIGNAL ;
    PORT
      LAYER M5 ;
        RECT  5.52 21.408 5.544 21.6 ;
    END
  END o0[6]
  PIN o0[70]
    DIRECTION OUTPUT ;
    USE SIGNAL ;
    PORT
      LAYER M5 ;
        RECT  16.704 21.408 16.728 21.6 ;
    END
  END o0[70]
  PIN o0[71]
    DIRECTION OUTPUT ;
    USE SIGNAL ;
    PORT
      LAYER M5 ;
        RECT  16.896 21.408 16.92 21.6 ;
    END
  END o0[71]
  PIN o0[72]
    DIRECTION OUTPUT ;
    USE SIGNAL ;
    PORT
      LAYER M5 ;
        RECT  17.04 21.408 17.064 21.6 ;
    END
  END o0[72]
  PIN o0[73]
    DIRECTION OUTPUT ;
    USE SIGNAL ;
    PORT
      LAYER M5 ;
        RECT  17.232 21.408 17.256 21.6 ;
    END
  END o0[73]
  PIN o0[74]
    DIRECTION OUTPUT ;
    USE SIGNAL ;
    PORT
      LAYER M5 ;
        RECT  17.376 21.408 17.4 21.6 ;
    END
  END o0[74]
  PIN o0[75]
    DIRECTION OUTPUT ;
    USE SIGNAL ;
    PORT
      LAYER M5 ;
        RECT  17.568 21.408 17.592 21.6 ;
    END
  END o0[75]
  PIN o0[76]
    DIRECTION OUTPUT ;
    USE SIGNAL ;
    PORT
      LAYER M5 ;
        RECT  17.712 21.408 17.736 21.6 ;
    END
  END o0[76]
  PIN o0[77]
    DIRECTION OUTPUT ;
    USE SIGNAL ;
    PORT
      LAYER M5 ;
        RECT  17.904 21.408 17.928 21.6 ;
    END
  END o0[77]
  PIN o0[78]
    DIRECTION OUTPUT ;
    USE SIGNAL ;
    PORT
      LAYER M5 ;
        RECT  18.096 21.408 18.12 21.6 ;
    END
  END o0[78]
  PIN o0[79]
    DIRECTION OUTPUT ;
    USE SIGNAL ;
    PORT
      LAYER M5 ;
        RECT  18.24 21.408 18.264 21.6 ;
    END
  END o0[79]
  PIN o0[7]
    DIRECTION OUTPUT ;
    USE SIGNAL ;
    PORT
      LAYER M5 ;
        RECT  5.712 21.408 5.736 21.6 ;
    END
  END o0[7]
  PIN o0[80]
    DIRECTION OUTPUT ;
    USE SIGNAL ;
    PORT
      LAYER M5 ;
        RECT  18.432 21.408 18.456 21.6 ;
    END
  END o0[80]
  PIN o0[81]
    DIRECTION OUTPUT ;
    USE SIGNAL ;
    PORT
      LAYER M5 ;
        RECT  18.576 21.408 18.6 21.6 ;
    END
  END o0[81]
  PIN o0[82]
    DIRECTION OUTPUT ;
    USE SIGNAL ;
    PORT
      LAYER M5 ;
        RECT  18.768 21.408 18.792 21.6 ;
    END
  END o0[82]
  PIN o0[83]
    DIRECTION OUTPUT ;
    USE SIGNAL ;
    PORT
      LAYER M5 ;
        RECT  18.96 21.408 18.984 21.6 ;
    END
  END o0[83]
  PIN o0[84]
    DIRECTION OUTPUT ;
    USE SIGNAL ;
    PORT
      LAYER M5 ;
        RECT  19.104 21.408 19.128 21.6 ;
    END
  END o0[84]
  PIN o0[85]
    DIRECTION OUTPUT ;
    USE SIGNAL ;
    PORT
      LAYER M5 ;
        RECT  19.296 21.408 19.32 21.6 ;
    END
  END o0[85]
  PIN o0[86]
    DIRECTION OUTPUT ;
    USE SIGNAL ;
    PORT
      LAYER M5 ;
        RECT  19.44 21.408 19.464 21.6 ;
    END
  END o0[86]
  PIN o0[87]
    DIRECTION OUTPUT ;
    USE SIGNAL ;
    PORT
      LAYER M5 ;
        RECT  19.632 21.408 19.656 21.6 ;
    END
  END o0[87]
  PIN o0[88]
    DIRECTION OUTPUT ;
    USE SIGNAL ;
    PORT
      LAYER M5 ;
        RECT  19.776 21.408 19.8 21.6 ;
    END
  END o0[88]
  PIN o0[89]
    DIRECTION OUTPUT ;
    USE SIGNAL ;
    PORT
      LAYER M5 ;
        RECT  19.968 21.408 19.992 21.6 ;
    END
  END o0[89]
  PIN o0[8]
    DIRECTION OUTPUT ;
    USE SIGNAL ;
    PORT
      LAYER M5 ;
        RECT  5.904 21.408 5.928 21.6 ;
    END
  END o0[8]
  PIN o0[90]
    DIRECTION OUTPUT ;
    USE SIGNAL ;
    PORT
      LAYER M5 ;
        RECT  20.16 21.408 20.184 21.6 ;
    END
  END o0[90]
  PIN o0[91]
    DIRECTION OUTPUT ;
    USE SIGNAL ;
    PORT
      LAYER M5 ;
        RECT  20.304 21.408 20.328 21.6 ;
    END
  END o0[91]
  PIN o0[92]
    DIRECTION OUTPUT ;
    USE SIGNAL ;
    PORT
      LAYER M5 ;
        RECT  20.496 21.408 20.52 21.6 ;
    END
  END o0[92]
  PIN o0[93]
    DIRECTION OUTPUT ;
    USE SIGNAL ;
    PORT
      LAYER M5 ;
        RECT  20.64 21.408 20.664 21.6 ;
    END
  END o0[93]
  PIN o0[94]
    DIRECTION OUTPUT ;
    USE SIGNAL ;
    PORT
      LAYER M5 ;
        RECT  20.832 21.408 20.856 21.6 ;
    END
  END o0[94]
  PIN o0[95]
    DIRECTION OUTPUT ;
    USE SIGNAL ;
    PORT
      LAYER M5 ;
        RECT  20.976 21.408 21 21.6 ;
    END
  END o0[95]
  PIN o0[96]
    DIRECTION OUTPUT ;
    USE SIGNAL ;
    PORT
      LAYER M5 ;
        RECT  21.168 21.408 21.192 21.6 ;
    END
  END o0[96]
  PIN o0[97]
    DIRECTION OUTPUT ;
    USE SIGNAL ;
    PORT
      LAYER M5 ;
        RECT  21.36 21.408 21.384 21.6 ;
    END
  END o0[97]
  PIN o0[98]
    DIRECTION OUTPUT ;
    USE SIGNAL ;
    PORT
      LAYER M5 ;
        RECT  21.504 21.408 21.528 21.6 ;
    END
  END o0[98]
  PIN o0[99]
    DIRECTION OUTPUT ;
    USE SIGNAL ;
    PORT
      LAYER M5 ;
        RECT  21.696 21.408 21.72 21.6 ;
    END
  END o0[99]
  PIN o0[9]
    DIRECTION OUTPUT ;
    USE SIGNAL ;
    PORT
      LAYER M5 ;
        RECT  6.048 21.408 6.072 21.6 ;
    END
  END o0[9]
  PIN o1[0]
    DIRECTION OUTPUT ;
    USE SIGNAL ;
    PORT
      LAYER M5 ;
        RECT  28.272 21.408 28.296 21.6 ;
    END
  END o1[0]
  PIN o1[100]
    DIRECTION OUTPUT ;
    USE SIGNAL ;
    PORT
      LAYER M5 ;
        RECT  45.6 21.408 45.624 21.6 ;
    END
  END o1[100]
  PIN o1[101]
    DIRECTION OUTPUT ;
    USE SIGNAL ;
    PORT
      LAYER M5 ;
        RECT  45.792 21.408 45.816 21.6 ;
    END
  END o1[101]
  PIN o1[102]
    DIRECTION OUTPUT ;
    USE SIGNAL ;
    PORT
      LAYER M5 ;
        RECT  45.936 21.408 45.96 21.6 ;
    END
  END o1[102]
  PIN o1[103]
    DIRECTION OUTPUT ;
    USE SIGNAL ;
    PORT
      LAYER M5 ;
        RECT  46.128 21.408 46.152 21.6 ;
    END
  END o1[103]
  PIN o1[104]
    DIRECTION OUTPUT ;
    USE SIGNAL ;
    PORT
      LAYER M5 ;
        RECT  46.32 21.408 46.344 21.6 ;
    END
  END o1[104]
  PIN o1[105]
    DIRECTION OUTPUT ;
    USE SIGNAL ;
    PORT
      LAYER M5 ;
        RECT  46.464 21.408 46.488 21.6 ;
    END
  END o1[105]
  PIN o1[106]
    DIRECTION OUTPUT ;
    USE SIGNAL ;
    PORT
      LAYER M5 ;
        RECT  46.656 21.408 46.68 21.6 ;
    END
  END o1[106]
  PIN o1[107]
    DIRECTION OUTPUT ;
    USE SIGNAL ;
    PORT
      LAYER M5 ;
        RECT  46.8 21.408 46.824 21.6 ;
    END
  END o1[107]
  PIN o1[108]
    DIRECTION OUTPUT ;
    USE SIGNAL ;
    PORT
      LAYER M5 ;
        RECT  46.992 21.408 47.016 21.6 ;
    END
  END o1[108]
  PIN o1[109]
    DIRECTION OUTPUT ;
    USE SIGNAL ;
    PORT
      LAYER M5 ;
        RECT  47.184 21.408 47.208 21.6 ;
    END
  END o1[109]
  PIN o1[10]
    DIRECTION OUTPUT ;
    USE SIGNAL ;
    PORT
      LAYER M5 ;
        RECT  30 21.408 30.024 21.6 ;
    END
  END o1[10]
  PIN o1[110]
    DIRECTION OUTPUT ;
    USE SIGNAL ;
    PORT
      LAYER M5 ;
        RECT  47.328 21.408 47.352 21.6 ;
    END
  END o1[110]
  PIN o1[111]
    DIRECTION OUTPUT ;
    USE SIGNAL ;
    PORT
      LAYER M5 ;
        RECT  47.52 21.408 47.544 21.6 ;
    END
  END o1[111]
  PIN o1[112]
    DIRECTION OUTPUT ;
    USE SIGNAL ;
    PORT
      LAYER M5 ;
        RECT  47.664 21.408 47.688 21.6 ;
    END
  END o1[112]
  PIN o1[113]
    DIRECTION OUTPUT ;
    USE SIGNAL ;
    PORT
      LAYER M5 ;
        RECT  47.856 21.408 47.88 21.6 ;
    END
  END o1[113]
  PIN o1[114]
    DIRECTION OUTPUT ;
    USE SIGNAL ;
    PORT
      LAYER M5 ;
        RECT  48 21.408 48.024 21.6 ;
    END
  END o1[114]
  PIN o1[115]
    DIRECTION OUTPUT ;
    USE SIGNAL ;
    PORT
      LAYER M5 ;
        RECT  48.192 21.408 48.216 21.6 ;
    END
  END o1[115]
  PIN o1[116]
    DIRECTION OUTPUT ;
    USE SIGNAL ;
    PORT
      LAYER M5 ;
        RECT  48.384 21.408 48.408 21.6 ;
    END
  END o1[116]
  PIN o1[117]
    DIRECTION OUTPUT ;
    USE SIGNAL ;
    PORT
      LAYER M5 ;
        RECT  48.528 21.408 48.552 21.6 ;
    END
  END o1[117]
  PIN o1[118]
    DIRECTION OUTPUT ;
    USE SIGNAL ;
    PORT
      LAYER M5 ;
        RECT  48.72 21.408 48.744 21.6 ;
    END
  END o1[118]
  PIN o1[119]
    DIRECTION OUTPUT ;
    USE SIGNAL ;
    PORT
      LAYER M5 ;
        RECT  48.864 21.408 48.888 21.6 ;
    END
  END o1[119]
  PIN o1[11]
    DIRECTION OUTPUT ;
    USE SIGNAL ;
    PORT
      LAYER M5 ;
        RECT  30.144 21.408 30.168 21.6 ;
    END
  END o1[11]
  PIN o1[120]
    DIRECTION OUTPUT ;
    USE SIGNAL ;
    PORT
      LAYER M5 ;
        RECT  49.056 21.408 49.08 21.6 ;
    END
  END o1[120]
  PIN o1[121]
    DIRECTION OUTPUT ;
    USE SIGNAL ;
    PORT
      LAYER M5 ;
        RECT  49.2 21.408 49.224 21.6 ;
    END
  END o1[121]
  PIN o1[122]
    DIRECTION OUTPUT ;
    USE SIGNAL ;
    PORT
      LAYER M5 ;
        RECT  49.392 21.408 49.416 21.6 ;
    END
  END o1[122]
  PIN o1[123]
    DIRECTION OUTPUT ;
    USE SIGNAL ;
    PORT
      LAYER M5 ;
        RECT  49.584 21.408 49.608 21.6 ;
    END
  END o1[123]
  PIN o1[124]
    DIRECTION OUTPUT ;
    USE SIGNAL ;
    PORT
      LAYER M5 ;
        RECT  49.728 21.408 49.752 21.6 ;
    END
  END o1[124]
  PIN o1[125]
    DIRECTION OUTPUT ;
    USE SIGNAL ;
    PORT
      LAYER M5 ;
        RECT  49.92 21.408 49.944 21.6 ;
    END
  END o1[125]
  PIN o1[126]
    DIRECTION OUTPUT ;
    USE SIGNAL ;
    PORT
      LAYER M5 ;
        RECT  50.064 21.408 50.088 21.6 ;
    END
  END o1[126]
  PIN o1[127]
    DIRECTION OUTPUT ;
    USE SIGNAL ;
    PORT
      LAYER M5 ;
        RECT  50.256 21.408 50.28 21.6 ;
    END
  END o1[127]
  PIN o1[128]
    DIRECTION OUTPUT ;
    USE SIGNAL ;
    PORT
      LAYER M5 ;
        RECT  50.448 21.408 50.472 21.6 ;
    END
  END o1[128]
  PIN o1[129]
    DIRECTION OUTPUT ;
    USE SIGNAL ;
    PORT
      LAYER M5 ;
        RECT  50.592 21.408 50.616 21.6 ;
    END
  END o1[129]
  PIN o1[12]
    DIRECTION OUTPUT ;
    USE SIGNAL ;
    PORT
      LAYER M5 ;
        RECT  30.336 21.408 30.36 21.6 ;
    END
  END o1[12]
  PIN o1[130]
    DIRECTION OUTPUT ;
    USE SIGNAL ;
    PORT
      LAYER M5 ;
        RECT  50.784 21.408 50.808 21.6 ;
    END
  END o1[130]
  PIN o1[131]
    DIRECTION OUTPUT ;
    USE SIGNAL ;
    PORT
      LAYER M5 ;
        RECT  50.928 21.408 50.952 21.6 ;
    END
  END o1[131]
  PIN o1[132]
    DIRECTION OUTPUT ;
    USE SIGNAL ;
    PORT
      LAYER M5 ;
        RECT  51.12 21.408 51.144 21.6 ;
    END
  END o1[132]
  PIN o1[133]
    DIRECTION OUTPUT ;
    USE SIGNAL ;
    PORT
      LAYER M5 ;
        RECT  51.264 21.408 51.288 21.6 ;
    END
  END o1[133]
  PIN o1[134]
    DIRECTION OUTPUT ;
    USE SIGNAL ;
    PORT
      LAYER M5 ;
        RECT  51.456 21.408 51.48 21.6 ;
    END
  END o1[134]
  PIN o1[135]
    DIRECTION OUTPUT ;
    USE SIGNAL ;
    PORT
      LAYER M5 ;
        RECT  51.648 21.408 51.672 21.6 ;
    END
  END o1[135]
  PIN o1[13]
    DIRECTION OUTPUT ;
    USE SIGNAL ;
    PORT
      LAYER M5 ;
        RECT  30.48 21.408 30.504 21.6 ;
    END
  END o1[13]
  PIN o1[14]
    DIRECTION OUTPUT ;
    USE SIGNAL ;
    PORT
      LAYER M5 ;
        RECT  30.672 21.408 30.696 21.6 ;
    END
  END o1[14]
  PIN o1[15]
    DIRECTION OUTPUT ;
    USE SIGNAL ;
    PORT
      LAYER M5 ;
        RECT  30.864 21.408 30.888 21.6 ;
    END
  END o1[15]
  PIN o1[16]
    DIRECTION OUTPUT ;
    USE SIGNAL ;
    PORT
      LAYER M5 ;
        RECT  31.008 21.408 31.032 21.6 ;
    END
  END o1[16]
  PIN o1[17]
    DIRECTION OUTPUT ;
    USE SIGNAL ;
    PORT
      LAYER M5 ;
        RECT  31.2 21.408 31.224 21.6 ;
    END
  END o1[17]
  PIN o1[18]
    DIRECTION OUTPUT ;
    USE SIGNAL ;
    PORT
      LAYER M5 ;
        RECT  31.344 21.408 31.368 21.6 ;
    END
  END o1[18]
  PIN o1[19]
    DIRECTION OUTPUT ;
    USE SIGNAL ;
    PORT
      LAYER M5 ;
        RECT  31.536 21.408 31.56 21.6 ;
    END
  END o1[19]
  PIN o1[1]
    DIRECTION OUTPUT ;
    USE SIGNAL ;
    PORT
      LAYER M5 ;
        RECT  28.416 21.408 28.44 21.6 ;
    END
  END o1[1]
  PIN o1[20]
    DIRECTION OUTPUT ;
    USE SIGNAL ;
    PORT
      LAYER M5 ;
        RECT  31.68 21.408 31.704 21.6 ;
    END
  END o1[20]
  PIN o1[21]
    DIRECTION OUTPUT ;
    USE SIGNAL ;
    PORT
      LAYER M5 ;
        RECT  31.872 21.408 31.896 21.6 ;
    END
  END o1[21]
  PIN o1[22]
    DIRECTION OUTPUT ;
    USE SIGNAL ;
    PORT
      LAYER M5 ;
        RECT  32.064 21.408 32.088 21.6 ;
    END
  END o1[22]
  PIN o1[23]
    DIRECTION OUTPUT ;
    USE SIGNAL ;
    PORT
      LAYER M5 ;
        RECT  32.208 21.408 32.232 21.6 ;
    END
  END o1[23]
  PIN o1[24]
    DIRECTION OUTPUT ;
    USE SIGNAL ;
    PORT
      LAYER M5 ;
        RECT  32.4 21.408 32.424 21.6 ;
    END
  END o1[24]
  PIN o1[25]
    DIRECTION OUTPUT ;
    USE SIGNAL ;
    PORT
      LAYER M5 ;
        RECT  32.544 21.408 32.568 21.6 ;
    END
  END o1[25]
  PIN o1[26]
    DIRECTION OUTPUT ;
    USE SIGNAL ;
    PORT
      LAYER M5 ;
        RECT  32.736 21.408 32.76 21.6 ;
    END
  END o1[26]
  PIN o1[27]
    DIRECTION OUTPUT ;
    USE SIGNAL ;
    PORT
      LAYER M5 ;
        RECT  32.928 21.408 32.952 21.6 ;
    END
  END o1[27]
  PIN o1[28]
    DIRECTION OUTPUT ;
    USE SIGNAL ;
    PORT
      LAYER M5 ;
        RECT  33.072 21.408 33.096 21.6 ;
    END
  END o1[28]
  PIN o1[29]
    DIRECTION OUTPUT ;
    USE SIGNAL ;
    PORT
      LAYER M5 ;
        RECT  33.264 21.408 33.288 21.6 ;
    END
  END o1[29]
  PIN o1[2]
    DIRECTION OUTPUT ;
    USE SIGNAL ;
    PORT
      LAYER M5 ;
        RECT  28.608 21.408 28.632 21.6 ;
    END
  END o1[2]
  PIN o1[30]
    DIRECTION OUTPUT ;
    USE SIGNAL ;
    PORT
      LAYER M5 ;
        RECT  33.408 21.408 33.432 21.6 ;
    END
  END o1[30]
  PIN o1[31]
    DIRECTION OUTPUT ;
    USE SIGNAL ;
    PORT
      LAYER M5 ;
        RECT  33.6 21.408 33.624 21.6 ;
    END
  END o1[31]
  PIN o1[32]
    DIRECTION OUTPUT ;
    USE SIGNAL ;
    PORT
      LAYER M5 ;
        RECT  33.744 21.408 33.768 21.6 ;
    END
  END o1[32]
  PIN o1[33]
    DIRECTION OUTPUT ;
    USE SIGNAL ;
    PORT
      LAYER M5 ;
        RECT  33.936 21.408 33.96 21.6 ;
    END
  END o1[33]
  PIN o1[34]
    DIRECTION OUTPUT ;
    USE SIGNAL ;
    PORT
      LAYER M5 ;
        RECT  34.128 21.408 34.152 21.6 ;
    END
  END o1[34]
  PIN o1[35]
    DIRECTION OUTPUT ;
    USE SIGNAL ;
    PORT
      LAYER M5 ;
        RECT  34.272 21.408 34.296 21.6 ;
    END
  END o1[35]
  PIN o1[36]
    DIRECTION OUTPUT ;
    USE SIGNAL ;
    PORT
      LAYER M5 ;
        RECT  34.464 21.408 34.488 21.6 ;
    END
  END o1[36]
  PIN o1[37]
    DIRECTION OUTPUT ;
    USE SIGNAL ;
    PORT
      LAYER M5 ;
        RECT  34.608 21.408 34.632 21.6 ;
    END
  END o1[37]
  PIN o1[38]
    DIRECTION OUTPUT ;
    USE SIGNAL ;
    PORT
      LAYER M5 ;
        RECT  34.8 21.408 34.824 21.6 ;
    END
  END o1[38]
  PIN o1[39]
    DIRECTION OUTPUT ;
    USE SIGNAL ;
    PORT
      LAYER M5 ;
        RECT  34.944 21.408 34.968 21.6 ;
    END
  END o1[39]
  PIN o1[3]
    DIRECTION OUTPUT ;
    USE SIGNAL ;
    PORT
      LAYER M5 ;
        RECT  28.8 21.408 28.824 21.6 ;
    END
  END o1[3]
  PIN o1[40]
    DIRECTION OUTPUT ;
    USE SIGNAL ;
    PORT
      LAYER M5 ;
        RECT  35.136 21.408 35.16 21.6 ;
    END
  END o1[40]
  PIN o1[41]
    DIRECTION OUTPUT ;
    USE SIGNAL ;
    PORT
      LAYER M5 ;
        RECT  35.328 21.408 35.352 21.6 ;
    END
  END o1[41]
  PIN o1[42]
    DIRECTION OUTPUT ;
    USE SIGNAL ;
    PORT
      LAYER M5 ;
        RECT  35.472 21.408 35.496 21.6 ;
    END
  END o1[42]
  PIN o1[43]
    DIRECTION OUTPUT ;
    USE SIGNAL ;
    PORT
      LAYER M5 ;
        RECT  35.664 21.408 35.688 21.6 ;
    END
  END o1[43]
  PIN o1[44]
    DIRECTION OUTPUT ;
    USE SIGNAL ;
    PORT
      LAYER M5 ;
        RECT  35.808 21.408 35.832 21.6 ;
    END
  END o1[44]
  PIN o1[45]
    DIRECTION OUTPUT ;
    USE SIGNAL ;
    PORT
      LAYER M5 ;
        RECT  36 21.408 36.024 21.6 ;
    END
  END o1[45]
  PIN o1[46]
    DIRECTION OUTPUT ;
    USE SIGNAL ;
    PORT
      LAYER M5 ;
        RECT  36.192 21.408 36.216 21.6 ;
    END
  END o1[46]
  PIN o1[47]
    DIRECTION OUTPUT ;
    USE SIGNAL ;
    PORT
      LAYER M5 ;
        RECT  36.336 21.408 36.36 21.6 ;
    END
  END o1[47]
  PIN o1[48]
    DIRECTION OUTPUT ;
    USE SIGNAL ;
    PORT
      LAYER M5 ;
        RECT  36.528 21.408 36.552 21.6 ;
    END
  END o1[48]
  PIN o1[49]
    DIRECTION OUTPUT ;
    USE SIGNAL ;
    PORT
      LAYER M5 ;
        RECT  36.672 21.408 36.696 21.6 ;
    END
  END o1[49]
  PIN o1[4]
    DIRECTION OUTPUT ;
    USE SIGNAL ;
    PORT
      LAYER M5 ;
        RECT  28.944 21.408 28.968 21.6 ;
    END
  END o1[4]
  PIN o1[50]
    DIRECTION OUTPUT ;
    USE SIGNAL ;
    PORT
      LAYER M5 ;
        RECT  36.864 21.408 36.888 21.6 ;
    END
  END o1[50]
  PIN o1[51]
    DIRECTION OUTPUT ;
    USE SIGNAL ;
    PORT
      LAYER M5 ;
        RECT  37.008 21.408 37.032 21.6 ;
    END
  END o1[51]
  PIN o1[52]
    DIRECTION OUTPUT ;
    USE SIGNAL ;
    PORT
      LAYER M5 ;
        RECT  37.2 21.408 37.224 21.6 ;
    END
  END o1[52]
  PIN o1[53]
    DIRECTION OUTPUT ;
    USE SIGNAL ;
    PORT
      LAYER M5 ;
        RECT  37.392 21.408 37.416 21.6 ;
    END
  END o1[53]
  PIN o1[54]
    DIRECTION OUTPUT ;
    USE SIGNAL ;
    PORT
      LAYER M5 ;
        RECT  37.536 21.408 37.56 21.6 ;
    END
  END o1[54]
  PIN o1[55]
    DIRECTION OUTPUT ;
    USE SIGNAL ;
    PORT
      LAYER M5 ;
        RECT  37.728 21.408 37.752 21.6 ;
    END
  END o1[55]
  PIN o1[56]
    DIRECTION OUTPUT ;
    USE SIGNAL ;
    PORT
      LAYER M5 ;
        RECT  37.872 21.408 37.896 21.6 ;
    END
  END o1[56]
  PIN o1[57]
    DIRECTION OUTPUT ;
    USE SIGNAL ;
    PORT
      LAYER M5 ;
        RECT  38.064 21.408 38.088 21.6 ;
    END
  END o1[57]
  PIN o1[58]
    DIRECTION OUTPUT ;
    USE SIGNAL ;
    PORT
      LAYER M5 ;
        RECT  38.208 21.408 38.232 21.6 ;
    END
  END o1[58]
  PIN o1[59]
    DIRECTION OUTPUT ;
    USE SIGNAL ;
    PORT
      LAYER M5 ;
        RECT  38.4 21.408 38.424 21.6 ;
    END
  END o1[59]
  PIN o1[5]
    DIRECTION OUTPUT ;
    USE SIGNAL ;
    PORT
      LAYER M5 ;
        RECT  29.136 21.408 29.16 21.6 ;
    END
  END o1[5]
  PIN o1[60]
    DIRECTION OUTPUT ;
    USE SIGNAL ;
    PORT
      LAYER M5 ;
        RECT  38.592 21.408 38.616 21.6 ;
    END
  END o1[60]
  PIN o1[61]
    DIRECTION OUTPUT ;
    USE SIGNAL ;
    PORT
      LAYER M5 ;
        RECT  38.736 21.408 38.76 21.6 ;
    END
  END o1[61]
  PIN o1[62]
    DIRECTION OUTPUT ;
    USE SIGNAL ;
    PORT
      LAYER M5 ;
        RECT  38.928 21.408 38.952 21.6 ;
    END
  END o1[62]
  PIN o1[63]
    DIRECTION OUTPUT ;
    USE SIGNAL ;
    PORT
      LAYER M5 ;
        RECT  39.072 21.408 39.096 21.6 ;
    END
  END o1[63]
  PIN o1[64]
    DIRECTION OUTPUT ;
    USE SIGNAL ;
    PORT
      LAYER M5 ;
        RECT  39.264 21.408 39.288 21.6 ;
    END
  END o1[64]
  PIN o1[65]
    DIRECTION OUTPUT ;
    USE SIGNAL ;
    PORT
      LAYER M5 ;
        RECT  39.456 21.408 39.48 21.6 ;
    END
  END o1[65]
  PIN o1[66]
    DIRECTION OUTPUT ;
    USE SIGNAL ;
    PORT
      LAYER M5 ;
        RECT  39.6 21.408 39.624 21.6 ;
    END
  END o1[66]
  PIN o1[67]
    DIRECTION OUTPUT ;
    USE SIGNAL ;
    PORT
      LAYER M5 ;
        RECT  39.792 21.408 39.816 21.6 ;
    END
  END o1[67]
  PIN o1[68]
    DIRECTION OUTPUT ;
    USE SIGNAL ;
    PORT
      LAYER M5 ;
        RECT  40.128 21.408 40.152 21.6 ;
    END
  END o1[68]
  PIN o1[69]
    DIRECTION OUTPUT ;
    USE SIGNAL ;
    PORT
      LAYER M5 ;
        RECT  40.272 21.408 40.296 21.6 ;
    END
  END o1[69]
  PIN o1[6]
    DIRECTION OUTPUT ;
    USE SIGNAL ;
    PORT
      LAYER M5 ;
        RECT  29.28 21.408 29.304 21.6 ;
    END
  END o1[6]
  PIN o1[70]
    DIRECTION OUTPUT ;
    USE SIGNAL ;
    PORT
      LAYER M5 ;
        RECT  40.464 21.408 40.488 21.6 ;
    END
  END o1[70]
  PIN o1[71]
    DIRECTION OUTPUT ;
    USE SIGNAL ;
    PORT
      LAYER M5 ;
        RECT  40.656 21.408 40.68 21.6 ;
    END
  END o1[71]
  PIN o1[72]
    DIRECTION OUTPUT ;
    USE SIGNAL ;
    PORT
      LAYER M5 ;
        RECT  40.8 21.408 40.824 21.6 ;
    END
  END o1[72]
  PIN o1[73]
    DIRECTION OUTPUT ;
    USE SIGNAL ;
    PORT
      LAYER M5 ;
        RECT  40.992 21.408 41.016 21.6 ;
    END
  END o1[73]
  PIN o1[74]
    DIRECTION OUTPUT ;
    USE SIGNAL ;
    PORT
      LAYER M5 ;
        RECT  41.136 21.408 41.16 21.6 ;
    END
  END o1[74]
  PIN o1[75]
    DIRECTION OUTPUT ;
    USE SIGNAL ;
    PORT
      LAYER M5 ;
        RECT  41.328 21.408 41.352 21.6 ;
    END
  END o1[75]
  PIN o1[76]
    DIRECTION OUTPUT ;
    USE SIGNAL ;
    PORT
      LAYER M5 ;
        RECT  41.472 21.408 41.496 21.6 ;
    END
  END o1[76]
  PIN o1[77]
    DIRECTION OUTPUT ;
    USE SIGNAL ;
    PORT
      LAYER M5 ;
        RECT  41.664 21.408 41.688 21.6 ;
    END
  END o1[77]
  PIN o1[78]
    DIRECTION OUTPUT ;
    USE SIGNAL ;
    PORT
      LAYER M5 ;
        RECT  41.856 21.408 41.88 21.6 ;
    END
  END o1[78]
  PIN o1[79]
    DIRECTION OUTPUT ;
    USE SIGNAL ;
    PORT
      LAYER M5 ;
        RECT  42 21.408 42.024 21.6 ;
    END
  END o1[79]
  PIN o1[7]
    DIRECTION OUTPUT ;
    USE SIGNAL ;
    PORT
      LAYER M5 ;
        RECT  29.472 21.408 29.496 21.6 ;
    END
  END o1[7]
  PIN o1[80]
    DIRECTION OUTPUT ;
    USE SIGNAL ;
    PORT
      LAYER M5 ;
        RECT  42.192 21.408 42.216 21.6 ;
    END
  END o1[80]
  PIN o1[81]
    DIRECTION OUTPUT ;
    USE SIGNAL ;
    PORT
      LAYER M5 ;
        RECT  42.336 21.408 42.36 21.6 ;
    END
  END o1[81]
  PIN o1[82]
    DIRECTION OUTPUT ;
    USE SIGNAL ;
    PORT
      LAYER M5 ;
        RECT  42.528 21.408 42.552 21.6 ;
    END
  END o1[82]
  PIN o1[83]
    DIRECTION OUTPUT ;
    USE SIGNAL ;
    PORT
      LAYER M5 ;
        RECT  42.72 21.408 42.744 21.6 ;
    END
  END o1[83]
  PIN o1[84]
    DIRECTION OUTPUT ;
    USE SIGNAL ;
    PORT
      LAYER M5 ;
        RECT  42.864 21.408 42.888 21.6 ;
    END
  END o1[84]
  PIN o1[85]
    DIRECTION OUTPUT ;
    USE SIGNAL ;
    PORT
      LAYER M5 ;
        RECT  43.056 21.408 43.08 21.6 ;
    END
  END o1[85]
  PIN o1[86]
    DIRECTION OUTPUT ;
    USE SIGNAL ;
    PORT
      LAYER M5 ;
        RECT  43.2 21.408 43.224 21.6 ;
    END
  END o1[86]
  PIN o1[87]
    DIRECTION OUTPUT ;
    USE SIGNAL ;
    PORT
      LAYER M5 ;
        RECT  43.392 21.408 43.416 21.6 ;
    END
  END o1[87]
  PIN o1[88]
    DIRECTION OUTPUT ;
    USE SIGNAL ;
    PORT
      LAYER M5 ;
        RECT  43.536 21.408 43.56 21.6 ;
    END
  END o1[88]
  PIN o1[89]
    DIRECTION OUTPUT ;
    USE SIGNAL ;
    PORT
      LAYER M5 ;
        RECT  43.728 21.408 43.752 21.6 ;
    END
  END o1[89]
  PIN o1[8]
    DIRECTION OUTPUT ;
    USE SIGNAL ;
    PORT
      LAYER M5 ;
        RECT  29.664 21.408 29.688 21.6 ;
    END
  END o1[8]
  PIN o1[90]
    DIRECTION OUTPUT ;
    USE SIGNAL ;
    PORT
      LAYER M5 ;
        RECT  43.92 21.408 43.944 21.6 ;
    END
  END o1[90]
  PIN o1[91]
    DIRECTION OUTPUT ;
    USE SIGNAL ;
    PORT
      LAYER M5 ;
        RECT  44.064 21.408 44.088 21.6 ;
    END
  END o1[91]
  PIN o1[92]
    DIRECTION OUTPUT ;
    USE SIGNAL ;
    PORT
      LAYER M5 ;
        RECT  44.256 21.408 44.28 21.6 ;
    END
  END o1[92]
  PIN o1[93]
    DIRECTION OUTPUT ;
    USE SIGNAL ;
    PORT
      LAYER M5 ;
        RECT  44.4 21.408 44.424 21.6 ;
    END
  END o1[93]
  PIN o1[94]
    DIRECTION OUTPUT ;
    USE SIGNAL ;
    PORT
      LAYER M5 ;
        RECT  44.592 21.408 44.616 21.6 ;
    END
  END o1[94]
  PIN o1[95]
    DIRECTION OUTPUT ;
    USE SIGNAL ;
    PORT
      LAYER M5 ;
        RECT  44.736 21.408 44.76 21.6 ;
    END
  END o1[95]
  PIN o1[96]
    DIRECTION OUTPUT ;
    USE SIGNAL ;
    PORT
      LAYER M5 ;
        RECT  44.928 21.408 44.952 21.6 ;
    END
  END o1[96]
  PIN o1[97]
    DIRECTION OUTPUT ;
    USE SIGNAL ;
    PORT
      LAYER M5 ;
        RECT  45.12 21.408 45.144 21.6 ;
    END
  END o1[97]
  PIN o1[98]
    DIRECTION OUTPUT ;
    USE SIGNAL ;
    PORT
      LAYER M5 ;
        RECT  45.264 21.408 45.288 21.6 ;
    END
  END o1[98]
  PIN o1[99]
    DIRECTION OUTPUT ;
    USE SIGNAL ;
    PORT
      LAYER M5 ;
        RECT  45.456 21.408 45.48 21.6 ;
    END
  END o1[99]
  PIN o1[9]
    DIRECTION OUTPUT ;
    USE SIGNAL ;
    PORT
      LAYER M5 ;
        RECT  29.808 21.408 29.832 21.6 ;
    END
  END o1[9]
  PIN o2[0]
    DIRECTION OUTPUT ;
    USE SIGNAL ;
    PORT
      LAYER M5 ;
        RECT  28.272 0 28.296 0.192 ;
    END
  END o2[0]
  PIN o2[100]
    DIRECTION OUTPUT ;
    USE SIGNAL ;
    PORT
      LAYER M5 ;
        RECT  45.6 0 45.624 0.192 ;
    END
  END o2[100]
  PIN o2[101]
    DIRECTION OUTPUT ;
    USE SIGNAL ;
    PORT
      LAYER M5 ;
        RECT  45.792 0 45.816 0.192 ;
    END
  END o2[101]
  PIN o2[102]
    DIRECTION OUTPUT ;
    USE SIGNAL ;
    PORT
      LAYER M5 ;
        RECT  45.936 0 45.96 0.192 ;
    END
  END o2[102]
  PIN o2[103]
    DIRECTION OUTPUT ;
    USE SIGNAL ;
    PORT
      LAYER M5 ;
        RECT  46.128 0 46.152 0.192 ;
    END
  END o2[103]
  PIN o2[104]
    DIRECTION OUTPUT ;
    USE SIGNAL ;
    PORT
      LAYER M5 ;
        RECT  46.32 0 46.344 0.192 ;
    END
  END o2[104]
  PIN o2[105]
    DIRECTION OUTPUT ;
    USE SIGNAL ;
    PORT
      LAYER M5 ;
        RECT  46.464 0 46.488 0.192 ;
    END
  END o2[105]
  PIN o2[106]
    DIRECTION OUTPUT ;
    USE SIGNAL ;
    PORT
      LAYER M5 ;
        RECT  46.656 0 46.68 0.192 ;
    END
  END o2[106]
  PIN o2[107]
    DIRECTION OUTPUT ;
    USE SIGNAL ;
    PORT
      LAYER M5 ;
        RECT  46.8 0 46.824 0.192 ;
    END
  END o2[107]
  PIN o2[108]
    DIRECTION OUTPUT ;
    USE SIGNAL ;
    PORT
      LAYER M5 ;
        RECT  46.992 0 47.016 0.192 ;
    END
  END o2[108]
  PIN o2[109]
    DIRECTION OUTPUT ;
    USE SIGNAL ;
    PORT
      LAYER M5 ;
        RECT  47.184 0 47.208 0.192 ;
    END
  END o2[109]
  PIN o2[10]
    DIRECTION OUTPUT ;
    USE SIGNAL ;
    PORT
      LAYER M5 ;
        RECT  30 0 30.024 0.192 ;
    END
  END o2[10]
  PIN o2[110]
    DIRECTION OUTPUT ;
    USE SIGNAL ;
    PORT
      LAYER M5 ;
        RECT  47.328 0 47.352 0.192 ;
    END
  END o2[110]
  PIN o2[111]
    DIRECTION OUTPUT ;
    USE SIGNAL ;
    PORT
      LAYER M5 ;
        RECT  47.52 0 47.544 0.192 ;
    END
  END o2[111]
  PIN o2[112]
    DIRECTION OUTPUT ;
    USE SIGNAL ;
    PORT
      LAYER M5 ;
        RECT  47.664 0 47.688 0.192 ;
    END
  END o2[112]
  PIN o2[113]
    DIRECTION OUTPUT ;
    USE SIGNAL ;
    PORT
      LAYER M5 ;
        RECT  47.856 0 47.88 0.192 ;
    END
  END o2[113]
  PIN o2[114]
    DIRECTION OUTPUT ;
    USE SIGNAL ;
    PORT
      LAYER M5 ;
        RECT  48 0 48.024 0.192 ;
    END
  END o2[114]
  PIN o2[115]
    DIRECTION OUTPUT ;
    USE SIGNAL ;
    PORT
      LAYER M5 ;
        RECT  48.192 0 48.216 0.192 ;
    END
  END o2[115]
  PIN o2[116]
    DIRECTION OUTPUT ;
    USE SIGNAL ;
    PORT
      LAYER M5 ;
        RECT  48.384 0 48.408 0.192 ;
    END
  END o2[116]
  PIN o2[117]
    DIRECTION OUTPUT ;
    USE SIGNAL ;
    PORT
      LAYER M5 ;
        RECT  48.528 0 48.552 0.192 ;
    END
  END o2[117]
  PIN o2[118]
    DIRECTION OUTPUT ;
    USE SIGNAL ;
    PORT
      LAYER M5 ;
        RECT  48.72 0 48.744 0.192 ;
    END
  END o2[118]
  PIN o2[119]
    DIRECTION OUTPUT ;
    USE SIGNAL ;
    PORT
      LAYER M5 ;
        RECT  48.864 0 48.888 0.192 ;
    END
  END o2[119]
  PIN o2[11]
    DIRECTION OUTPUT ;
    USE SIGNAL ;
    PORT
      LAYER M5 ;
        RECT  30.144 0 30.168 0.192 ;
    END
  END o2[11]
  PIN o2[120]
    DIRECTION OUTPUT ;
    USE SIGNAL ;
    PORT
      LAYER M5 ;
        RECT  49.056 0 49.08 0.192 ;
    END
  END o2[120]
  PIN o2[121]
    DIRECTION OUTPUT ;
    USE SIGNAL ;
    PORT
      LAYER M5 ;
        RECT  49.2 0 49.224 0.192 ;
    END
  END o2[121]
  PIN o2[122]
    DIRECTION OUTPUT ;
    USE SIGNAL ;
    PORT
      LAYER M5 ;
        RECT  49.392 0 49.416 0.192 ;
    END
  END o2[122]
  PIN o2[123]
    DIRECTION OUTPUT ;
    USE SIGNAL ;
    PORT
      LAYER M5 ;
        RECT  49.584 0 49.608 0.192 ;
    END
  END o2[123]
  PIN o2[124]
    DIRECTION OUTPUT ;
    USE SIGNAL ;
    PORT
      LAYER M5 ;
        RECT  49.728 0 49.752 0.192 ;
    END
  END o2[124]
  PIN o2[125]
    DIRECTION OUTPUT ;
    USE SIGNAL ;
    PORT
      LAYER M5 ;
        RECT  49.92 0 49.944 0.192 ;
    END
  END o2[125]
  PIN o2[126]
    DIRECTION OUTPUT ;
    USE SIGNAL ;
    PORT
      LAYER M5 ;
        RECT  50.064 0 50.088 0.192 ;
    END
  END o2[126]
  PIN o2[127]
    DIRECTION OUTPUT ;
    USE SIGNAL ;
    PORT
      LAYER M5 ;
        RECT  50.256 0 50.28 0.192 ;
    END
  END o2[127]
  PIN o2[128]
    DIRECTION OUTPUT ;
    USE SIGNAL ;
    PORT
      LAYER M5 ;
        RECT  50.448 0 50.472 0.192 ;
    END
  END o2[128]
  PIN o2[129]
    DIRECTION OUTPUT ;
    USE SIGNAL ;
    PORT
      LAYER M5 ;
        RECT  50.592 0 50.616 0.192 ;
    END
  END o2[129]
  PIN o2[12]
    DIRECTION OUTPUT ;
    USE SIGNAL ;
    PORT
      LAYER M5 ;
        RECT  30.336 0 30.36 0.192 ;
    END
  END o2[12]
  PIN o2[130]
    DIRECTION OUTPUT ;
    USE SIGNAL ;
    PORT
      LAYER M5 ;
        RECT  50.784 0 50.808 0.192 ;
    END
  END o2[130]
  PIN o2[131]
    DIRECTION OUTPUT ;
    USE SIGNAL ;
    PORT
      LAYER M5 ;
        RECT  50.928 0 50.952 0.192 ;
    END
  END o2[131]
  PIN o2[132]
    DIRECTION OUTPUT ;
    USE SIGNAL ;
    PORT
      LAYER M5 ;
        RECT  51.12 0 51.144 0.192 ;
    END
  END o2[132]
  PIN o2[133]
    DIRECTION OUTPUT ;
    USE SIGNAL ;
    PORT
      LAYER M5 ;
        RECT  51.264 0 51.288 0.192 ;
    END
  END o2[133]
  PIN o2[134]
    DIRECTION OUTPUT ;
    USE SIGNAL ;
    PORT
      LAYER M5 ;
        RECT  51.456 0 51.48 0.192 ;
    END
  END o2[134]
  PIN o2[135]
    DIRECTION OUTPUT ;
    USE SIGNAL ;
    PORT
      LAYER M5 ;
        RECT  51.648 0 51.672 0.192 ;
    END
  END o2[135]
  PIN o2[13]
    DIRECTION OUTPUT ;
    USE SIGNAL ;
    PORT
      LAYER M5 ;
        RECT  30.48 0 30.504 0.192 ;
    END
  END o2[13]
  PIN o2[14]
    DIRECTION OUTPUT ;
    USE SIGNAL ;
    PORT
      LAYER M5 ;
        RECT  30.672 0 30.696 0.192 ;
    END
  END o2[14]
  PIN o2[15]
    DIRECTION OUTPUT ;
    USE SIGNAL ;
    PORT
      LAYER M5 ;
        RECT  30.864 0 30.888 0.192 ;
    END
  END o2[15]
  PIN o2[16]
    DIRECTION OUTPUT ;
    USE SIGNAL ;
    PORT
      LAYER M5 ;
        RECT  31.008 0 31.032 0.192 ;
    END
  END o2[16]
  PIN o2[17]
    DIRECTION OUTPUT ;
    USE SIGNAL ;
    PORT
      LAYER M5 ;
        RECT  31.2 0 31.224 0.192 ;
    END
  END o2[17]
  PIN o2[18]
    DIRECTION OUTPUT ;
    USE SIGNAL ;
    PORT
      LAYER M5 ;
        RECT  31.344 0 31.368 0.192 ;
    END
  END o2[18]
  PIN o2[19]
    DIRECTION OUTPUT ;
    USE SIGNAL ;
    PORT
      LAYER M5 ;
        RECT  31.536 0 31.56 0.192 ;
    END
  END o2[19]
  PIN o2[1]
    DIRECTION OUTPUT ;
    USE SIGNAL ;
    PORT
      LAYER M5 ;
        RECT  28.416 0 28.44 0.192 ;
    END
  END o2[1]
  PIN o2[20]
    DIRECTION OUTPUT ;
    USE SIGNAL ;
    PORT
      LAYER M5 ;
        RECT  31.68 0 31.704 0.192 ;
    END
  END o2[20]
  PIN o2[21]
    DIRECTION OUTPUT ;
    USE SIGNAL ;
    PORT
      LAYER M5 ;
        RECT  31.872 0 31.896 0.192 ;
    END
  END o2[21]
  PIN o2[22]
    DIRECTION OUTPUT ;
    USE SIGNAL ;
    PORT
      LAYER M5 ;
        RECT  32.064 0 32.088 0.192 ;
    END
  END o2[22]
  PIN o2[23]
    DIRECTION OUTPUT ;
    USE SIGNAL ;
    PORT
      LAYER M5 ;
        RECT  32.208 0 32.232 0.192 ;
    END
  END o2[23]
  PIN o2[24]
    DIRECTION OUTPUT ;
    USE SIGNAL ;
    PORT
      LAYER M5 ;
        RECT  32.4 0 32.424 0.192 ;
    END
  END o2[24]
  PIN o2[25]
    DIRECTION OUTPUT ;
    USE SIGNAL ;
    PORT
      LAYER M5 ;
        RECT  32.544 0 32.568 0.192 ;
    END
  END o2[25]
  PIN o2[26]
    DIRECTION OUTPUT ;
    USE SIGNAL ;
    PORT
      LAYER M5 ;
        RECT  32.736 0 32.76 0.192 ;
    END
  END o2[26]
  PIN o2[27]
    DIRECTION OUTPUT ;
    USE SIGNAL ;
    PORT
      LAYER M5 ;
        RECT  32.928 0 32.952 0.192 ;
    END
  END o2[27]
  PIN o2[28]
    DIRECTION OUTPUT ;
    USE SIGNAL ;
    PORT
      LAYER M5 ;
        RECT  33.072 0 33.096 0.192 ;
    END
  END o2[28]
  PIN o2[29]
    DIRECTION OUTPUT ;
    USE SIGNAL ;
    PORT
      LAYER M5 ;
        RECT  33.264 0 33.288 0.192 ;
    END
  END o2[29]
  PIN o2[2]
    DIRECTION OUTPUT ;
    USE SIGNAL ;
    PORT
      LAYER M5 ;
        RECT  28.608 0 28.632 0.192 ;
    END
  END o2[2]
  PIN o2[30]
    DIRECTION OUTPUT ;
    USE SIGNAL ;
    PORT
      LAYER M5 ;
        RECT  33.408 0 33.432 0.192 ;
    END
  END o2[30]
  PIN o2[31]
    DIRECTION OUTPUT ;
    USE SIGNAL ;
    PORT
      LAYER M5 ;
        RECT  33.6 0 33.624 0.192 ;
    END
  END o2[31]
  PIN o2[32]
    DIRECTION OUTPUT ;
    USE SIGNAL ;
    PORT
      LAYER M5 ;
        RECT  33.744 0 33.768 0.192 ;
    END
  END o2[32]
  PIN o2[33]
    DIRECTION OUTPUT ;
    USE SIGNAL ;
    PORT
      LAYER M5 ;
        RECT  33.936 0 33.96 0.192 ;
    END
  END o2[33]
  PIN o2[34]
    DIRECTION OUTPUT ;
    USE SIGNAL ;
    PORT
      LAYER M5 ;
        RECT  34.128 0 34.152 0.192 ;
    END
  END o2[34]
  PIN o2[35]
    DIRECTION OUTPUT ;
    USE SIGNAL ;
    PORT
      LAYER M5 ;
        RECT  34.272 0 34.296 0.192 ;
    END
  END o2[35]
  PIN o2[36]
    DIRECTION OUTPUT ;
    USE SIGNAL ;
    PORT
      LAYER M5 ;
        RECT  34.464 0 34.488 0.192 ;
    END
  END o2[36]
  PIN o2[37]
    DIRECTION OUTPUT ;
    USE SIGNAL ;
    PORT
      LAYER M5 ;
        RECT  34.608 0 34.632 0.192 ;
    END
  END o2[37]
  PIN o2[38]
    DIRECTION OUTPUT ;
    USE SIGNAL ;
    PORT
      LAYER M5 ;
        RECT  34.8 0 34.824 0.192 ;
    END
  END o2[38]
  PIN o2[39]
    DIRECTION OUTPUT ;
    USE SIGNAL ;
    PORT
      LAYER M5 ;
        RECT  34.944 0 34.968 0.192 ;
    END
  END o2[39]
  PIN o2[3]
    DIRECTION OUTPUT ;
    USE SIGNAL ;
    PORT
      LAYER M5 ;
        RECT  28.8 0 28.824 0.192 ;
    END
  END o2[3]
  PIN o2[40]
    DIRECTION OUTPUT ;
    USE SIGNAL ;
    PORT
      LAYER M5 ;
        RECT  35.136 0 35.16 0.192 ;
    END
  END o2[40]
  PIN o2[41]
    DIRECTION OUTPUT ;
    USE SIGNAL ;
    PORT
      LAYER M5 ;
        RECT  35.328 0 35.352 0.192 ;
    END
  END o2[41]
  PIN o2[42]
    DIRECTION OUTPUT ;
    USE SIGNAL ;
    PORT
      LAYER M5 ;
        RECT  35.472 0 35.496 0.192 ;
    END
  END o2[42]
  PIN o2[43]
    DIRECTION OUTPUT ;
    USE SIGNAL ;
    PORT
      LAYER M5 ;
        RECT  35.664 0 35.688 0.192 ;
    END
  END o2[43]
  PIN o2[44]
    DIRECTION OUTPUT ;
    USE SIGNAL ;
    PORT
      LAYER M5 ;
        RECT  35.808 0 35.832 0.192 ;
    END
  END o2[44]
  PIN o2[45]
    DIRECTION OUTPUT ;
    USE SIGNAL ;
    PORT
      LAYER M5 ;
        RECT  36 0 36.024 0.192 ;
    END
  END o2[45]
  PIN o2[46]
    DIRECTION OUTPUT ;
    USE SIGNAL ;
    PORT
      LAYER M5 ;
        RECT  36.192 0 36.216 0.192 ;
    END
  END o2[46]
  PIN o2[47]
    DIRECTION OUTPUT ;
    USE SIGNAL ;
    PORT
      LAYER M5 ;
        RECT  36.336 0 36.36 0.192 ;
    END
  END o2[47]
  PIN o2[48]
    DIRECTION OUTPUT ;
    USE SIGNAL ;
    PORT
      LAYER M5 ;
        RECT  36.528 0 36.552 0.192 ;
    END
  END o2[48]
  PIN o2[49]
    DIRECTION OUTPUT ;
    USE SIGNAL ;
    PORT
      LAYER M5 ;
        RECT  36.672 0 36.696 0.192 ;
    END
  END o2[49]
  PIN o2[4]
    DIRECTION OUTPUT ;
    USE SIGNAL ;
    PORT
      LAYER M5 ;
        RECT  28.944 0 28.968 0.192 ;
    END
  END o2[4]
  PIN o2[50]
    DIRECTION OUTPUT ;
    USE SIGNAL ;
    PORT
      LAYER M5 ;
        RECT  36.864 0 36.888 0.192 ;
    END
  END o2[50]
  PIN o2[51]
    DIRECTION OUTPUT ;
    USE SIGNAL ;
    PORT
      LAYER M5 ;
        RECT  37.008 0 37.032 0.192 ;
    END
  END o2[51]
  PIN o2[52]
    DIRECTION OUTPUT ;
    USE SIGNAL ;
    PORT
      LAYER M5 ;
        RECT  37.2 0 37.224 0.192 ;
    END
  END o2[52]
  PIN o2[53]
    DIRECTION OUTPUT ;
    USE SIGNAL ;
    PORT
      LAYER M5 ;
        RECT  37.392 0 37.416 0.192 ;
    END
  END o2[53]
  PIN o2[54]
    DIRECTION OUTPUT ;
    USE SIGNAL ;
    PORT
      LAYER M5 ;
        RECT  37.536 0 37.56 0.192 ;
    END
  END o2[54]
  PIN o2[55]
    DIRECTION OUTPUT ;
    USE SIGNAL ;
    PORT
      LAYER M5 ;
        RECT  37.728 0 37.752 0.192 ;
    END
  END o2[55]
  PIN o2[56]
    DIRECTION OUTPUT ;
    USE SIGNAL ;
    PORT
      LAYER M5 ;
        RECT  37.872 0 37.896 0.192 ;
    END
  END o2[56]
  PIN o2[57]
    DIRECTION OUTPUT ;
    USE SIGNAL ;
    PORT
      LAYER M5 ;
        RECT  38.064 0 38.088 0.192 ;
    END
  END o2[57]
  PIN o2[58]
    DIRECTION OUTPUT ;
    USE SIGNAL ;
    PORT
      LAYER M5 ;
        RECT  38.208 0 38.232 0.192 ;
    END
  END o2[58]
  PIN o2[59]
    DIRECTION OUTPUT ;
    USE SIGNAL ;
    PORT
      LAYER M5 ;
        RECT  38.4 0 38.424 0.192 ;
    END
  END o2[59]
  PIN o2[5]
    DIRECTION OUTPUT ;
    USE SIGNAL ;
    PORT
      LAYER M5 ;
        RECT  29.136 0 29.16 0.192 ;
    END
  END o2[5]
  PIN o2[60]
    DIRECTION OUTPUT ;
    USE SIGNAL ;
    PORT
      LAYER M5 ;
        RECT  38.592 0 38.616 0.192 ;
    END
  END o2[60]
  PIN o2[61]
    DIRECTION OUTPUT ;
    USE SIGNAL ;
    PORT
      LAYER M5 ;
        RECT  38.736 0 38.76 0.192 ;
    END
  END o2[61]
  PIN o2[62]
    DIRECTION OUTPUT ;
    USE SIGNAL ;
    PORT
      LAYER M5 ;
        RECT  38.928 0 38.952 0.192 ;
    END
  END o2[62]
  PIN o2[63]
    DIRECTION OUTPUT ;
    USE SIGNAL ;
    PORT
      LAYER M5 ;
        RECT  39.072 0 39.096 0.192 ;
    END
  END o2[63]
  PIN o2[64]
    DIRECTION OUTPUT ;
    USE SIGNAL ;
    PORT
      LAYER M5 ;
        RECT  39.264 0 39.288 0.192 ;
    END
  END o2[64]
  PIN o2[65]
    DIRECTION OUTPUT ;
    USE SIGNAL ;
    PORT
      LAYER M5 ;
        RECT  39.456 0 39.48 0.192 ;
    END
  END o2[65]
  PIN o2[66]
    DIRECTION OUTPUT ;
    USE SIGNAL ;
    PORT
      LAYER M5 ;
        RECT  39.6 0 39.624 0.192 ;
    END
  END o2[66]
  PIN o2[67]
    DIRECTION OUTPUT ;
    USE SIGNAL ;
    PORT
      LAYER M5 ;
        RECT  39.792 0 39.816 0.192 ;
    END
  END o2[67]
  PIN o2[68]
    DIRECTION OUTPUT ;
    USE SIGNAL ;
    PORT
      LAYER M5 ;
        RECT  40.128 0 40.152 0.192 ;
    END
  END o2[68]
  PIN o2[69]
    DIRECTION OUTPUT ;
    USE SIGNAL ;
    PORT
      LAYER M5 ;
        RECT  40.272 0 40.296 0.192 ;
    END
  END o2[69]
  PIN o2[6]
    DIRECTION OUTPUT ;
    USE SIGNAL ;
    PORT
      LAYER M5 ;
        RECT  29.28 0 29.304 0.192 ;
    END
  END o2[6]
  PIN o2[70]
    DIRECTION OUTPUT ;
    USE SIGNAL ;
    PORT
      LAYER M5 ;
        RECT  40.464 0 40.488 0.192 ;
    END
  END o2[70]
  PIN o2[71]
    DIRECTION OUTPUT ;
    USE SIGNAL ;
    PORT
      LAYER M5 ;
        RECT  40.656 0 40.68 0.192 ;
    END
  END o2[71]
  PIN o2[72]
    DIRECTION OUTPUT ;
    USE SIGNAL ;
    PORT
      LAYER M5 ;
        RECT  40.8 0 40.824 0.192 ;
    END
  END o2[72]
  PIN o2[73]
    DIRECTION OUTPUT ;
    USE SIGNAL ;
    PORT
      LAYER M5 ;
        RECT  40.992 0 41.016 0.192 ;
    END
  END o2[73]
  PIN o2[74]
    DIRECTION OUTPUT ;
    USE SIGNAL ;
    PORT
      LAYER M5 ;
        RECT  41.136 0 41.16 0.192 ;
    END
  END o2[74]
  PIN o2[75]
    DIRECTION OUTPUT ;
    USE SIGNAL ;
    PORT
      LAYER M5 ;
        RECT  41.328 0 41.352 0.192 ;
    END
  END o2[75]
  PIN o2[76]
    DIRECTION OUTPUT ;
    USE SIGNAL ;
    PORT
      LAYER M5 ;
        RECT  41.472 0 41.496 0.192 ;
    END
  END o2[76]
  PIN o2[77]
    DIRECTION OUTPUT ;
    USE SIGNAL ;
    PORT
      LAYER M5 ;
        RECT  41.664 0 41.688 0.192 ;
    END
  END o2[77]
  PIN o2[78]
    DIRECTION OUTPUT ;
    USE SIGNAL ;
    PORT
      LAYER M5 ;
        RECT  41.856 0 41.88 0.192 ;
    END
  END o2[78]
  PIN o2[79]
    DIRECTION OUTPUT ;
    USE SIGNAL ;
    PORT
      LAYER M5 ;
        RECT  42 0 42.024 0.192 ;
    END
  END o2[79]
  PIN o2[7]
    DIRECTION OUTPUT ;
    USE SIGNAL ;
    PORT
      LAYER M5 ;
        RECT  29.472 0 29.496 0.192 ;
    END
  END o2[7]
  PIN o2[80]
    DIRECTION OUTPUT ;
    USE SIGNAL ;
    PORT
      LAYER M5 ;
        RECT  42.192 0 42.216 0.192 ;
    END
  END o2[80]
  PIN o2[81]
    DIRECTION OUTPUT ;
    USE SIGNAL ;
    PORT
      LAYER M5 ;
        RECT  42.336 0 42.36 0.192 ;
    END
  END o2[81]
  PIN o2[82]
    DIRECTION OUTPUT ;
    USE SIGNAL ;
    PORT
      LAYER M5 ;
        RECT  42.528 0 42.552 0.192 ;
    END
  END o2[82]
  PIN o2[83]
    DIRECTION OUTPUT ;
    USE SIGNAL ;
    PORT
      LAYER M5 ;
        RECT  42.72 0 42.744 0.192 ;
    END
  END o2[83]
  PIN o2[84]
    DIRECTION OUTPUT ;
    USE SIGNAL ;
    PORT
      LAYER M5 ;
        RECT  42.864 0 42.888 0.192 ;
    END
  END o2[84]
  PIN o2[85]
    DIRECTION OUTPUT ;
    USE SIGNAL ;
    PORT
      LAYER M5 ;
        RECT  43.056 0 43.08 0.192 ;
    END
  END o2[85]
  PIN o2[86]
    DIRECTION OUTPUT ;
    USE SIGNAL ;
    PORT
      LAYER M5 ;
        RECT  43.2 0 43.224 0.192 ;
    END
  END o2[86]
  PIN o2[87]
    DIRECTION OUTPUT ;
    USE SIGNAL ;
    PORT
      LAYER M5 ;
        RECT  43.392 0 43.416 0.192 ;
    END
  END o2[87]
  PIN o2[88]
    DIRECTION OUTPUT ;
    USE SIGNAL ;
    PORT
      LAYER M5 ;
        RECT  43.536 0 43.56 0.192 ;
    END
  END o2[88]
  PIN o2[89]
    DIRECTION OUTPUT ;
    USE SIGNAL ;
    PORT
      LAYER M5 ;
        RECT  43.728 0 43.752 0.192 ;
    END
  END o2[89]
  PIN o2[8]
    DIRECTION OUTPUT ;
    USE SIGNAL ;
    PORT
      LAYER M5 ;
        RECT  29.664 0 29.688 0.192 ;
    END
  END o2[8]
  PIN o2[90]
    DIRECTION OUTPUT ;
    USE SIGNAL ;
    PORT
      LAYER M5 ;
        RECT  43.92 0 43.944 0.192 ;
    END
  END o2[90]
  PIN o2[91]
    DIRECTION OUTPUT ;
    USE SIGNAL ;
    PORT
      LAYER M5 ;
        RECT  44.064 0 44.088 0.192 ;
    END
  END o2[91]
  PIN o2[92]
    DIRECTION OUTPUT ;
    USE SIGNAL ;
    PORT
      LAYER M5 ;
        RECT  44.256 0 44.28 0.192 ;
    END
  END o2[92]
  PIN o2[93]
    DIRECTION OUTPUT ;
    USE SIGNAL ;
    PORT
      LAYER M5 ;
        RECT  44.4 0 44.424 0.192 ;
    END
  END o2[93]
  PIN o2[94]
    DIRECTION OUTPUT ;
    USE SIGNAL ;
    PORT
      LAYER M5 ;
        RECT  44.592 0 44.616 0.192 ;
    END
  END o2[94]
  PIN o2[95]
    DIRECTION OUTPUT ;
    USE SIGNAL ;
    PORT
      LAYER M5 ;
        RECT  44.736 0 44.76 0.192 ;
    END
  END o2[95]
  PIN o2[96]
    DIRECTION OUTPUT ;
    USE SIGNAL ;
    PORT
      LAYER M5 ;
        RECT  44.928 0 44.952 0.192 ;
    END
  END o2[96]
  PIN o2[97]
    DIRECTION OUTPUT ;
    USE SIGNAL ;
    PORT
      LAYER M5 ;
        RECT  45.12 0 45.144 0.192 ;
    END
  END o2[97]
  PIN o2[98]
    DIRECTION OUTPUT ;
    USE SIGNAL ;
    PORT
      LAYER M5 ;
        RECT  45.264 0 45.288 0.192 ;
    END
  END o2[98]
  PIN o2[99]
    DIRECTION OUTPUT ;
    USE SIGNAL ;
    PORT
      LAYER M5 ;
        RECT  45.456 0 45.48 0.192 ;
    END
  END o2[99]
  PIN o2[9]
    DIRECTION OUTPUT ;
    USE SIGNAL ;
    PORT
      LAYER M5 ;
        RECT  29.808 0 29.832 0.192 ;
    END
  END o2[9]
  PIN rs
    DIRECTION INPUT ;
    USE SIGNAL ;
    PORT
      LAYER M4 ;
        RECT  0 10.8 0.192 10.824 ;
    END
  END rs
  PIN VDD
    DIRECTION INOUT ;
    USE POWER ;
    PORT
      LAYER M5 ;
        RECT  53.892 2.151 54.012 19.449 ;
        RECT  51.192 2.151 51.312 19.449 ;
        RECT  48.492 2.151 48.612 19.449 ;
        RECT  45.792 2.151 45.912 19.449 ;
        RECT  43.092 2.151 43.212 19.449 ;
        RECT  40.392 2.151 40.512 19.449 ;
        RECT  37.692 2.151 37.812 19.449 ;
        RECT  34.992 2.151 35.112 19.449 ;
        RECT  32.292 2.151 32.412 19.449 ;
        RECT  29.592 2.151 29.712 19.449 ;
        RECT  26.892 2.151 27.012 19.449 ;
        RECT  24.192 2.151 24.312 19.449 ;
        RECT  21.492 2.151 21.612 19.449 ;
        RECT  18.792 2.151 18.912 19.449 ;
        RECT  16.092 2.151 16.212 19.449 ;
        RECT  13.392 2.151 13.512 19.449 ;
        RECT  10.692 2.151 10.812 19.449 ;
        RECT  7.992 2.151 8.112 19.449 ;
        RECT  5.292 2.151 5.412 19.449 ;
        RECT  2.592 2.151 2.712 19.449 ;
    END
  END VDD
  PIN VSS
    DIRECTION INOUT ;
    USE GROUND ;
    PORT
      LAYER M5 ;
        RECT  53.7 2.137 53.82 19.463 ;
        RECT  51 2.137 51.12 19.463 ;
        RECT  48.3 2.137 48.42 19.463 ;
        RECT  45.6 2.137 45.72 19.463 ;
        RECT  42.9 2.137 43.02 19.463 ;
        RECT  40.2 2.137 40.32 19.463 ;
        RECT  37.5 2.137 37.62 19.463 ;
        RECT  34.8 2.137 34.92 19.463 ;
        RECT  32.1 2.137 32.22 19.463 ;
        RECT  29.4 2.137 29.52 19.463 ;
        RECT  26.7 2.137 26.82 19.463 ;
        RECT  24 2.137 24.12 19.463 ;
        RECT  21.3 2.137 21.42 19.463 ;
        RECT  18.6 2.137 18.72 19.463 ;
        RECT  15.9 2.137 16.02 19.463 ;
        RECT  13.2 2.137 13.32 19.463 ;
        RECT  10.5 2.137 10.62 19.463 ;
        RECT  7.8 2.137 7.92 19.463 ;
        RECT  5.1 2.137 5.22 19.463 ;
        RECT  2.4 2.137 2.52 19.463 ;
    END
  END VSS
  OBS
    LAYER RVTN ;
     RECT  2.16 2.16 54 2.295 ;
     RECT  2.16 2.565 54 2.835 ;
     RECT  2.16 3.105 54 3.375 ;
     RECT  2.16 3.645 54 3.915 ;
     RECT  2.16 4.185 54 4.455 ;
     RECT  2.16 4.725 54 4.995 ;
     RECT  2.16 5.265 54 5.535 ;
     RECT  2.16 5.805 54 6.075 ;
     RECT  2.16 6.345 54 6.615 ;
     RECT  2.16 6.885 54 7.155 ;
     RECT  2.16 7.425 54 7.695 ;
     RECT  2.16 7.965 54 8.235 ;
     RECT  2.16 8.505 54 8.775 ;
     RECT  2.16 9.045 54 9.315 ;
     RECT  2.16 9.585 54 9.855 ;
     RECT  2.16 10.125 54 10.395 ;
     RECT  2.16 10.665 54 10.935 ;
     RECT  2.16 11.205 54 11.475 ;
     RECT  2.16 11.745 54 12.015 ;
     RECT  2.16 12.285 54 12.555 ;
     RECT  2.16 12.825 54 13.095 ;
     RECT  2.16 13.365 54 13.635 ;
     RECT  2.16 13.905 54 14.175 ;
     RECT  2.16 14.445 54 14.715 ;
     RECT  2.16 14.985 54 15.255 ;
     RECT  2.16 15.525 54 15.795 ;
     RECT  2.16 16.065 54 16.335 ;
     RECT  2.16 16.605 54 16.875 ;
     RECT  2.16 17.145 54 17.415 ;
     RECT  2.16 17.685 54 17.955 ;
     RECT  2.16 18.225 54 18.495 ;
     RECT  2.16 18.765 54 19.035 ;
     RECT  2.16 19.305 54 19.44 ;
    LAYER RVTP ;
     RECT  2.16 2.295 54 2.565 ;
     RECT  2.16 2.835 54 3.105 ;
     RECT  2.16 3.375 54 3.645 ;
     RECT  2.16 3.915 54 4.185 ;
     RECT  2.16 4.455 54 4.725 ;
     RECT  2.16 4.995 54 5.265 ;
     RECT  2.16 5.535 54 5.805 ;
     RECT  2.16 6.075 54 6.345 ;
     RECT  2.16 6.615 54 6.885 ;
     RECT  2.16 7.155 54 7.425 ;
     RECT  2.16 7.695 54 7.965 ;
     RECT  2.16 8.235 54 8.505 ;
     RECT  2.16 8.775 54 9.045 ;
     RECT  2.16 9.315 54 9.585 ;
     RECT  2.16 9.855 54 10.125 ;
     RECT  2.16 10.395 54 10.665 ;
     RECT  2.16 10.935 54 11.205 ;
     RECT  2.16 11.475 54 11.745 ;
     RECT  2.16 12.015 54 12.285 ;
     RECT  2.16 12.555 54 12.825 ;
     RECT  2.16 13.095 54 13.365 ;
     RECT  2.16 13.635 54 13.905 ;
     RECT  2.16 14.175 54 14.445 ;
     RECT  2.16 14.715 54 14.985 ;
     RECT  2.16 15.255 54 15.525 ;
     RECT  2.16 15.795 54 16.065 ;
     RECT  2.16 16.335 54 16.605 ;
     RECT  2.16 16.875 54 17.145 ;
     RECT  2.16 17.415 54 17.685 ;
     RECT  2.16 17.955 54 18.225 ;
     RECT  2.16 18.495 54 18.765 ;
     RECT  2.16 19.035 54 19.305 ;
    LAYER M1 ;
     RECT  2.16 2.151 54 19.449 ;
    LAYER M2 ;
     RECT  0.211 9.63 2.16 9.648 ;
     RECT  2.16 2.151 4.891 19.449 ;
     RECT  4.891 2.07 5.207 19.449 ;
     RECT  5.207 2.151 9.931 19.449 ;
     RECT  9.931 2.106 11.183 19.449 ;
     RECT  11.183 2.151 15.007 19.449 ;
     RECT  15.007 2.034 25.087 19.449 ;
     RECT  25.087 1.962 27.067 19.449 ;
     RECT  27.067 1.692 27.383 19.449 ;
     RECT  28.147 1.152 28.283 1.17 ;
     RECT  27.383 1.962 28.579 19.449 ;
     RECT  28.579 1.881 30.335 19.449 ;
     RECT  30.335 2.034 35.699 19.449 ;
     RECT  35.699 2.07 50.135 19.449 ;
     RECT  50.135 2.151 54 19.449 ;
     RECT  54 2.421 54.012 19.179 ;
    LAYER M3 ;
     RECT  39.816 0.187 40.086 0.235 ;
     RECT  27.432 0.475 27.45 0.523 ;
     RECT  29.844 0.187 29.862 0.523 ;
     RECT  30.708 0.187 30.726 0.523 ;
     RECT  34.164 0.187 37.242 0.523 ;
     RECT  38.664 0.187 38.682 0.523 ;
     RECT  41.364 0.187 41.49 0.523 ;
     RECT  45.468 0.187 46.89 0.523 ;
     RECT  48.204 0.187 50.31 0.523 ;
     RECT  40.896 0.523 41.49 0.571 ;
     RECT  4.68 0.187 4.698 1.099 ;
     RECT  5.688 0.523 5.706 1.099 ;
     RECT  27.36 0.523 27.45 1.099 ;
     RECT  28.728 0.523 28.746 1.099 ;
     RECT  29.844 0.523 30.726 1.099 ;
     RECT  31.572 0.187 32.274 1.099 ;
     RECT  38.052 0.523 38.898 1.099 ;
     RECT  39.816 0.235 40.158 1.099 ;
     RECT  40.896 0.571 41.67 1.099 ;
     RECT  42.732 0.187 44.622 1.099 ;
     RECT  45.468 0.523 50.31 1.099 ;
     RECT  33.588 0.523 37.242 1.147 ;
     RECT  27.36 1.099 30.726 1.675 ;
     RECT  31.572 1.099 32.67 1.675 ;
     RECT  33.444 1.147 37.242 1.675 ;
     RECT  38.052 1.099 50.31 1.675 ;
     RECT  27.36 1.675 32.67 1.687 ;
     RECT  4.68 1.099 5.706 1.723 ;
     RECT  11.448 0.571 11.466 1.723 ;
     RECT  16.38 1.627 16.398 1.723 ;
     RECT  27.072 1.687 32.67 1.723 ;
     RECT  33.444 1.675 50.922 1.723 ;
     RECT  51.66 0.571 51.678 1.723 ;
     RECT  17.64 1.723 20.79 1.771 ;
     RECT  21.564 1.723 51.786 1.771 ;
     RECT  4.608 1.723 16.83 2.101 ;
     RECT  17.64 1.771 51.786 2.101 ;
     RECT  4.608 2.101 51.786 2.227 ;
     RECT  2.415 2.143 2.505 2.413 ;
     RECT  53.715 2.143 53.805 2.413 ;
     RECT  4.14 2.227 51.786 2.803 ;
     RECT  3.96 2.803 51.786 2.861 ;
     RECT  4.14 2.861 51.786 3.677 ;
     RECT  3.42 3.979 3.618 4.379 ;
     RECT  4.392 3.677 51.786 4.379 ;
     RECT  3.42 4.379 3.438 4.451 ;
     RECT  4.392 4.379 51.678 4.459 ;
     RECT  4.356 4.459 51.678 4.496 ;
     RECT  4.392 4.496 51.678 4.523 ;
     RECT  4.5 4.523 51.678 4.649 ;
     RECT  2.415 2.413 2.697 5.575 ;
     RECT  2.415 5.575 3.114 8.159 ;
     RECT  2.415 8.159 2.697 8.275 ;
     RECT  2.376 8.275 2.697 9.509 ;
     RECT  0.216 9.625 0.234 10.829 ;
     RECT  4.5 4.649 51.297 18.121 ;
     RECT  4.5 18.121 51.75 18.149 ;
     RECT  4.644 18.149 51.75 19.139 ;
     RECT  2.415 9.509 2.697 19.187 ;
     RECT  53.715 2.413 53.997 19.187 ;
     RECT  4.644 19.139 24.498 19.339 ;
     RECT  25.272 19.139 51.75 19.345 ;
     RECT  4.536 19.339 24.498 19.379 ;
     RECT  4.752 19.379 17.01 19.421 ;
     RECT  19.8 19.379 24.498 19.421 ;
     RECT  25.272 19.345 51.822 19.421 ;
     RECT  2.415 19.187 2.505 19.457 ;
     RECT  7.2 19.421 17.01 19.457 ;
     RECT  17.784 19.379 18.705 19.457 ;
     RECT  53.715 19.187 53.805 19.457 ;
     RECT  17.784 19.457 18.594 19.565 ;
     RECT  19.8 19.421 21.474 19.613 ;
     RECT  25.272 19.421 47.358 19.613 ;
     RECT  4.752 19.421 6.138 19.997 ;
     RECT  7.2 19.457 12.726 19.997 ;
     RECT  13.536 19.457 17.01 19.997 ;
     RECT  17.784 19.565 18.198 19.997 ;
     RECT  19.8 19.613 20.79 19.997 ;
     RECT  22.716 19.421 24.498 19.997 ;
     RECT  25.272 19.613 26.01 19.997 ;
     RECT  27.144 19.613 47.358 19.997 ;
     RECT  48.096 19.421 51.822 19.997 ;
     RECT  8.676 19.997 8.91 20.045 ;
     RECT  27.144 19.997 28.494 20.045 ;
     RECT  29.268 19.997 31.842 20.045 ;
     RECT  33.048 19.997 47.358 20.045 ;
     RECT  13.536 19.997 13.554 20.093 ;
     RECT  14.508 19.997 15.21 20.093 ;
     RECT  4.752 19.997 4.77 20.573 ;
     RECT  5.868 19.997 5.886 20.573 ;
     RECT  7.452 19.997 7.47 20.573 ;
     RECT  8.676 20.045 8.694 20.573 ;
     RECT  11.16 19.997 11.178 20.573 ;
     RECT  12.456 19.997 12.474 20.573 ;
     RECT  14.508 20.093 14.562 20.573 ;
     RECT  16.056 19.997 16.794 20.573 ;
     RECT  18.18 19.997 18.198 20.573 ;
     RECT  20.448 19.997 20.79 20.573 ;
     RECT  23.076 19.997 23.094 20.573 ;
     RECT  23.976 19.997 24.498 20.573 ;
     RECT  28.44 20.045 28.494 20.573 ;
     RECT  29.268 20.045 30.582 20.573 ;
     RECT  31.5 20.045 31.842 20.573 ;
     RECT  33.048 20.045 44.082 20.573 ;
     RECT  44.856 20.045 47.358 20.573 ;
     RECT  48.096 19.997 48.294 20.573 ;
     RECT  49.248 19.997 49.374 20.573 ;
     RECT  50.364 19.997 50.994 20.573 ;
     RECT  29.34 20.573 29.358 20.621 ;
     RECT  30.564 20.573 30.582 20.621 ;
     RECT  34.596 20.573 35.154 20.621 ;
     RECT  40.032 20.573 40.05 20.621 ;
     RECT  41.22 20.573 41.238 20.621 ;
     RECT  42.408 20.573 42.426 20.621 ;
     RECT  47.232 20.573 47.25 20.621 ;
     RECT  48.276 20.573 48.294 20.621 ;
     RECT  14.508 20.573 14.526 20.669 ;
     RECT  28.44 20.573 28.458 20.669 ;
     RECT  50.904 20.573 50.994 20.669 ;
     RECT  50.976 20.669 50.994 20.717 ;
    LAYER M4 ;
     RECT  0.156 10.8 0.245 10.824 ;
     RECT  2.408 2.148 2.512 19.452 ;
     RECT  2.512 2.418 2.704 19.182 ;
     RECT  2.704 2.688 3.925 2.712 ;
     RECT  2.704 3.984 3.925 4.056 ;
     RECT  3.925 2.688 3.971 4.056 ;
     RECT  3.971 2.688 4.381 3.432 ;
     RECT  4.381 2.256 4.597 3.432 ;
     RECT  4.345 4.464 4.7 4.488 ;
     RECT  4.645 20.544 4.781 20.568 ;
     RECT  4.501 19.344 4.837 19.368 ;
     RECT  4.837 18.816 4.988 19.368 ;
     RECT  4.741 6.288 5.065 6.312 ;
     RECT  4.669 0.192 5.075 0.216 ;
     RECT  4.597 1.728 5.108 3.432 ;
     RECT  4.7 4.464 5.108 4.536 ;
     RECT  5.065 6.288 5.108 6.84 ;
     RECT  4.988 18.816 5.108 19.992 ;
     RECT  5.108 1.728 5.132 19.992 ;
     RECT  5.132 0.528 5.219 19.992 ;
     RECT  5.219 1.728 5.404 19.992 ;
     RECT  5.404 18.72 5.573 19.992 ;
     RECT  5.573 18.816 5.852 19.992 ;
     RECT  5.852 18.816 5.939 20.568 ;
     RECT  5.404 1.728 6.005 7.416 ;
     RECT  5.219 0.528 6.083 0.552 ;
     RECT  6.005 6.816 6.113 7.416 ;
     RECT  5.939 18.816 6.149 19.992 ;
     RECT  6.149 18.816 6.509 19.416 ;
     RECT  6.509 18.816 6.565 18.84 ;
     RECT  6.565 18.144 6.833 18.84 ;
     RECT  6.005 1.728 6.973 5.832 ;
     RECT  6.113 6.816 6.973 7.368 ;
     RECT  6.901 15.072 7.093 15.096 ;
     RECT  7.189 19.968 7.429 19.992 ;
     RECT  7.429 19.968 7.516 20.568 ;
     RECT  7.516 19.968 7.724 20.04 ;
     RECT  6.973 1.728 7.808 7.368 ;
     RECT  7.093 15.072 7.808 15.384 ;
     RECT  6.833 18.144 7.808 18.168 ;
     RECT  7.724 19.584 7.808 20.04 ;
     RECT  7.808 1.728 8.104 20.04 ;
     RECT  8.104 1.728 8.489 7.944 ;
     RECT  8.104 19.968 8.665 20.04 ;
     RECT  8.665 19.968 8.819 20.568 ;
     RECT  8.819 19.968 8.921 20.04 ;
     RECT  8.104 18.24 9.065 18.84 ;
     RECT  9.065 18.816 9.157 18.84 ;
     RECT  8.921 19.968 9.157 19.992 ;
     RECT  8.489 1.728 9.457 1.8 ;
     RECT  9.457 1.728 9.565 1.848 ;
     RECT  8.489 2.88 9.565 7.944 ;
     RECT  9.565 1.728 10.508 7.944 ;
     RECT  9.829 15.216 10.508 15.24 ;
     RECT  9.157 18.816 10.508 19.992 ;
     RECT  10.508 1.728 10.804 19.992 ;
     RECT  10.804 18.816 10.837 19.992 ;
     RECT  10.837 18.816 11.189 20.568 ;
     RECT  10.804 15.216 11.477 15.384 ;
     RECT  11.437 0.576 11.747 0.6 ;
     RECT  11.861 17.664 11.945 17.688 ;
     RECT  11.189 18.816 12.161 19.992 ;
     RECT  12.161 19.968 12.229 19.992 ;
     RECT  11.477 15.36 12.293 15.384 ;
     RECT  12.229 19.968 12.485 20.568 ;
     RECT  12.161 18.816 13.093 18.888 ;
     RECT  10.804 1.728 13.208 7.368 ;
     RECT  12.293 15.36 13.208 15.432 ;
     RECT  13.093 18.24 13.208 18.888 ;
     RECT  12.485 19.968 13.208 20.088 ;
     RECT  13.208 1.728 13.504 20.088 ;
     RECT  13.504 1.728 14.003 7.944 ;
     RECT  13.504 18.816 14.249 18.936 ;
     RECT  13.504 19.968 14.293 20.088 ;
     RECT  14.293 19.968 14.437 20.568 ;
     RECT  14.437 19.968 14.537 20.664 ;
     RECT  14.537 19.968 14.573 20.568 ;
     RECT  14.629 15.072 14.732 15.096 ;
     RECT  14.732 15.072 14.819 15.432 ;
     RECT  14.819 15.072 14.861 15.096 ;
     RECT  14.003 1.728 15.253 7.656 ;
     RECT  14.821 18.768 15.301 18.792 ;
     RECT  15.301 18.768 15.788 18.84 ;
     RECT  14.573 19.968 15.788 20.088 ;
     RECT  15.788 18.768 15.875 20.088 ;
     RECT  15.253 1.728 15.908 7.944 ;
     RECT  15.073 10.8 15.908 10.824 ;
     RECT  15.875 18.768 15.908 19.56 ;
     RECT  15.908 1.728 16.204 19.56 ;
     RECT  16.204 1.728 16.325 7.656 ;
     RECT  16.325 1.632 16.409 7.656 ;
     RECT  16.405 0.288 16.547 0.312 ;
     RECT  16.021 20.544 16.805 20.568 ;
     RECT  16.204 18.816 16.885 19.56 ;
     RECT  16.885 18.816 17.381 19.992 ;
     RECT  17.381 18.816 17.413 18.936 ;
     RECT  17.269 10.8 17.417 10.824 ;
     RECT  17.413 18.24 17.497 18.936 ;
     RECT  16.409 1.728 17.665 7.656 ;
     RECT  17.665 1.728 17.708 7.704 ;
     RECT  17.381 19.968 18.085 19.992 ;
     RECT  18.085 19.968 18.209 20.568 ;
     RECT  17.708 1.728 18.236 7.752 ;
     RECT  17.497 18.816 18.385 18.936 ;
     RECT  18.236 1.728 18.608 7.944 ;
     RECT  17.365 15.36 18.608 15.384 ;
     RECT  18.385 18.816 18.608 19.608 ;
     RECT  18.608 1.728 18.904 19.608 ;
     RECT  18.904 18.816 19.429 19.608 ;
     RECT  19.429 18.816 19.829 19.992 ;
     RECT  18.904 1.728 19.933 7.896 ;
     RECT  19.829 18.816 20.401 19.416 ;
     RECT  19.957 20.544 20.801 20.568 ;
     RECT  20.401 18.24 21.121 19.416 ;
     RECT  19.933 1.728 21.308 7.992 ;
     RECT  20.293 15.36 21.308 15.384 ;
     RECT  21.121 18.24 21.308 19.56 ;
     RECT  21.308 1.728 21.349 19.56 ;
     RECT  21.109 0.288 21.395 0.312 ;
     RECT  21.349 1.728 21.485 19.608 ;
     RECT  21.485 1.728 21.539 19.56 ;
     RECT  21.539 1.728 21.604 19.416 ;
     RECT  21.604 10.8 22.133 10.824 ;
     RECT  21.604 18.816 22.169 19.416 ;
     RECT  22.169 18.816 22.205 18.936 ;
     RECT  21.604 15.36 22.385 15.384 ;
     RECT  22.549 19.968 22.885 19.992 ;
     RECT  21.604 1.728 23.029 7.992 ;
     RECT  22.205 18.816 23.221 18.84 ;
     RECT  23.221 18.816 23.317 18.936 ;
     RECT  22.885 19.968 23.317 20.568 ;
     RECT  23.029 1.728 24.008 8.04 ;
     RECT  23.317 18.816 24.008 20.568 ;
     RECT  24.008 1.728 24.275 20.568 ;
     RECT  24.275 1.728 24.304 19.182 ;
     RECT  24.304 16.368 24.419 16.584 ;
     RECT  24.304 10.8 24.515 10.824 ;
     RECT  24.275 20.544 24.659 20.568 ;
     RECT  24.304 1.728 25.043 8.04 ;
     RECT  24.419 16.368 25.301 16.488 ;
     RECT  25.301 16.368 25.333 16.392 ;
     RECT  24.304 18.816 25.388 18.936 ;
     RECT  25.244 19.968 25.388 19.992 ;
     RECT  25.388 18.816 25.475 19.992 ;
     RECT  25.333 15.984 25.621 16.392 ;
     RECT  25.475 18.816 25.661 18.888 ;
     RECT  25.661 18.816 25.813 18.84 ;
     RECT  25.621 15.888 26.293 16.392 ;
     RECT  25.813 18.24 26.636 18.84 ;
     RECT  25.475 19.968 26.636 19.992 ;
     RECT  25.043 1.728 26.708 7.944 ;
     RECT  26.293 15.312 26.708 16.392 ;
     RECT  26.636 18.24 26.708 19.992 ;
     RECT  26.708 1.728 26.821 19.992 ;
     RECT  26.821 1.728 27.004 20.04 ;
     RECT  27.004 1.728 27.101 7.992 ;
     RECT  27.349 0.528 27.421 0.552 ;
     RECT  27.004 18.24 27.785 20.04 ;
     RECT  27.785 18.816 27.929 20.04 ;
     RECT  27.421 0.48 28.141 0.552 ;
     RECT  27.101 1.728 28.141 7.944 ;
     RECT  28.141 0.48 28.307 7.944 ;
     RECT  27.929 19.248 28.429 20.04 ;
     RECT  28.429 19.248 28.835 20.664 ;
     RECT  28.835 19.248 29.269 20.616 ;
     RECT  28.307 0.48 29.329 0.552 ;
     RECT  28.307 1.632 29.329 7.944 ;
     RECT  29.329 0.48 29.408 7.944 ;
     RECT  27.004 16.368 29.408 16.392 ;
     RECT  29.269 18.816 29.408 20.616 ;
     RECT  29.408 0.48 29.507 20.616 ;
     RECT  29.507 0.48 29.653 0.552 ;
     RECT  29.507 1.68 29.704 20.616 ;
     RECT  29.704 18.768 29.843 20.616 ;
     RECT  29.843 18.768 30.035 19.416 ;
     RECT  29.653 0.192 30.179 0.552 ;
     RECT  30.035 18.768 30.385 18.792 ;
     RECT  29.843 20.544 30.707 20.616 ;
     RECT  29.704 15.984 30.809 16.536 ;
     RECT  30.809 15.984 30.899 16.392 ;
     RECT  30.707 20.544 30.949 20.568 ;
     RECT  30.179 0.192 31.628 0.216 ;
     RECT  29.704 1.68 31.628 7.944 ;
     RECT  30.949 19.968 31.853 20.568 ;
     RECT  31.853 19.968 31.861 19.992 ;
     RECT  31.628 0.192 32.108 7.944 ;
     RECT  30.899 16.368 32.108 16.392 ;
     RECT  31.165 18.24 32.108 18.264 ;
     RECT  31.861 19.344 32.108 19.992 ;
     RECT  32.108 0.192 32.285 19.992 ;
     RECT  32.285 1.104 32.404 19.992 ;
     RECT  32.404 18.24 32.476 19.992 ;
     RECT  32.476 18.24 32.771 18.84 ;
     RECT  32.771 18.816 32.963 18.84 ;
     RECT  32.476 19.968 33.02 19.992 ;
     RECT  32.404 1.104 33.548 7.944 ;
     RECT  33.548 0.528 34.109 7.944 ;
     RECT  33.02 19.968 34.553 20.568 ;
     RECT  34.553 20.544 34.585 20.568 ;
     RECT  34.549 18.24 34.621 18.264 ;
     RECT  32.404 16.368 34.685 16.392 ;
     RECT  34.109 0.192 34.808 7.944 ;
     RECT  34.685 15.408 34.808 16.392 ;
     RECT  34.621 17.664 34.808 18.264 ;
     RECT  34.808 0.192 34.912 19.452 ;
     RECT  34.912 0.192 35.104 19.416 ;
     RECT  35.104 0.192 35.201 7.944 ;
     RECT  34.585 20.544 35.363 20.616 ;
     RECT  35.104 18.816 35.921 19.416 ;
     RECT  35.104 14.832 36.001 14.856 ;
     RECT  35.201 1.728 36.169 7.944 ;
     RECT  35.201 0.192 36.457 0.6 ;
     RECT  36.169 1.68 36.457 7.944 ;
     RECT  35.921 19.392 36.517 19.416 ;
     RECT  35.363 20.544 36.517 20.568 ;
     RECT  36.457 0.192 36.563 7.944 ;
     RECT  36.517 19.392 36.605 20.568 ;
     RECT  36.563 0.192 37.253 0.216 ;
     RECT  36.709 18.24 37.34 18.264 ;
     RECT  36.605 19.392 37.34 19.452 ;
     RECT  36.563 1.68 37.508 7.944 ;
     RECT  35.104 16.368 37.508 16.392 ;
     RECT  37.34 18.24 37.508 19.452 ;
     RECT  37.508 1.68 37.717 19.452 ;
     RECT  37.717 1.68 37.804 19.56 ;
     RECT  37.804 19.392 37.82 19.56 ;
     RECT  36.605 20.544 37.82 20.568 ;
     RECT  37.717 0.288 38.012 0.312 ;
     RECT  38.012 0.288 38.357 0.552 ;
     RECT  37.804 1.68 38.629 7.944 ;
     RECT  38.357 0.288 38.653 0.6 ;
     RECT  38.653 0.192 38.771 0.6 ;
     RECT  37.804 16.368 38.801 16.536 ;
     RECT  38.771 0.528 39.041 0.6 ;
     RECT  39.013 18.24 39.097 18.264 ;
     RECT  37.82 19.392 39.157 20.568 ;
     RECT  39.041 0.528 39.299 1.176 ;
     RECT  38.629 2.256 39.877 7.944 ;
     RECT  39.877 1.728 39.971 7.944 ;
     RECT  39.157 18.816 40.021 20.568 ;
     RECT  39.761 0.192 40.163 0.264 ;
     RECT  39.971 2.148 40.208 7.944 ;
     RECT  38.801 16.368 40.208 16.392 ;
     RECT  40.021 18.816 40.208 20.616 ;
     RECT  40.163 0.24 40.307 0.264 ;
     RECT  40.208 2.148 40.312 20.616 ;
     RECT  40.312 2.256 40.421 20.616 ;
     RECT  40.421 2.418 40.504 20.616 ;
     RECT  40.504 2.544 40.565 7.944 ;
     RECT  40.453 0.528 40.601 1.176 ;
     RECT  40.601 0.528 40.835 1.128 ;
     RECT  40.504 18.768 40.835 18.792 ;
     RECT  40.565 7.92 40.961 7.944 ;
     RECT  40.565 2.544 41.213 6.84 ;
     RECT  40.835 0.528 41.309 0.6 ;
     RECT  40.504 19.968 41.363 20.616 ;
     RECT  41.309 0.192 41.545 0.6 ;
     RECT  41.213 2.544 41.717 6.024 ;
     RECT  41.717 2.544 41.749 3.672 ;
     RECT  41.363 19.968 41.857 20.568 ;
     RECT  41.749 1.68 41.891 3.672 ;
     RECT  41.845 18.24 41.933 18.264 ;
     RECT  41.545 0.576 41.948 0.6 ;
     RECT  41.857 19.392 42.37 20.568 ;
     RECT  42.37 19.392 42.563 20.616 ;
     RECT  41.948 0.576 42.677 1.128 ;
     RECT  41.891 2.256 42.908 3.672 ;
     RECT  41.717 4.704 42.908 6.024 ;
     RECT  40.504 16.368 42.908 16.392 ;
     RECT  42.563 19.392 42.908 20.568 ;
     RECT  42.677 0.192 43.045 1.128 ;
     RECT  42.908 2.148 43.045 20.568 ;
     RECT  43.045 0.192 43.091 20.568 ;
     RECT  43.091 0.192 43.129 19.182 ;
     RECT  43.129 2.418 43.204 19.182 ;
     RECT  43.129 0.192 43.265 1.176 ;
     RECT  43.204 3.312 43.337 3.672 ;
     RECT  43.265 0.192 43.571 1.128 ;
     RECT  43.204 4.704 43.625 5.88 ;
     RECT  43.204 18.768 43.777 18.84 ;
     RECT  43.625 4.704 44.165 5.496 ;
     RECT  44.245 19.152 44.305 19.416 ;
     RECT  43.091 20.544 44.305 20.568 ;
     RECT  44.305 19.152 44.476 20.568 ;
     RECT  44.377 1.728 44.557 1.752 ;
     RECT  43.571 0.192 44.876 0.552 ;
     RECT  44.557 1.728 44.876 2.28 ;
     RECT  44.876 0.192 45.155 2.28 ;
     RECT  44.476 19.392 45.155 20.568 ;
     RECT  45.155 0.192 45.299 1.128 ;
     RECT  45.155 2.148 45.608 2.28 ;
     RECT  43.337 3.36 45.608 3.672 ;
     RECT  44.165 4.704 45.608 5.208 ;
     RECT  43.204 16.368 45.608 16.392 ;
     RECT  45.155 19.392 45.608 19.452 ;
     RECT  45.608 2.148 45.712 19.452 ;
     RECT  45.712 2.256 45.904 19.452 ;
     RECT  45.904 4.704 46.067 5.64 ;
     RECT  45.904 16.368 46.067 16.584 ;
     RECT  45.904 2.256 46.163 3.672 ;
     RECT  46.067 4.752 46.217 5.64 ;
     RECT  45.904 18.816 46.309 19.452 ;
     RECT  45.155 20.544 46.309 20.568 ;
     RECT  45.299 0.192 46.412 0.216 ;
     RECT  46.217 5.184 46.883 5.64 ;
     RECT  46.309 18.816 46.933 20.568 ;
     RECT  46.883 5.184 46.937 5.592 ;
     RECT  46.067 16.368 46.944 16.392 ;
     RECT  46.412 0.192 47.027 0.552 ;
     RECT  46.933 18.768 47.027 20.568 ;
     RECT  47.027 18.816 47.221 20.568 ;
     RECT  47.077 1.728 47.329 1.752 ;
     RECT  47.329 1.728 47.365 2.28 ;
     RECT  46.163 3.648 47.365 3.672 ;
     RECT  47.365 1.728 47.581 3.672 ;
     RECT  47.581 1.68 47.699 3.672 ;
     RECT  47.027 0.528 48.149 0.552 ;
     RECT  47.699 1.728 48.308 3.672 ;
     RECT  47.365 15.984 48.308 16.008 ;
     RECT  47.221 18.816 48.308 20.616 ;
     RECT  48.308 1.728 48.419 20.616 ;
     RECT  48.149 0.192 48.481 0.552 ;
     RECT  48.419 2.256 48.563 20.616 ;
     RECT  48.563 2.256 48.604 20.568 ;
     RECT  48.604 2.256 49.235 2.28 ;
     RECT  48.604 19.392 49.849 20.568 ;
     RECT  49.849 18.768 49.955 20.568 ;
     RECT  48.481 0.192 50.021 0.6 ;
     RECT  50.021 0.192 50.105 1.176 ;
     RECT  50.105 0.192 50.321 0.216 ;
     RECT  50.317 1.68 50.732 1.752 ;
     RECT  49.955 19.392 50.893 20.568 ;
     RECT  50.732 1.68 50.963 2.28 ;
     RECT  50.893 19.392 50.965 20.664 ;
     RECT  50.963 1.728 51.008 2.28 ;
     RECT  50.965 19.392 51.008 20.712 ;
     RECT  51.008 1.728 51.299 20.712 ;
     RECT  51.299 1.728 51.304 19.992 ;
     RECT  51.445 0.576 51.689 0.6 ;
     RECT  51.304 1.728 51.797 1.752 ;
     RECT  51.304 19.968 51.833 19.992 ;
     RECT  53.708 2.148 53.812 19.452 ;
     RECT  53.812 2.418 54.004 19.182 ;
    LAYER M5 ;
     RECT  4.512 0.144 51.672 0.563 ;
     RECT  4.512 0.563 46.152 1.139 ;
     RECT  4.512 1.139 43.224 1.187 ;
     RECT  47.184 0.563 51.672 1.187 ;
     RECT  4.512 1.187 43.08 1.715 ;
     RECT  28.944 1.715 33.288 1.763 ;
     RECT  34.608 1.715 35.688 1.763 ;
     RECT  37.008 1.715 41.16 1.763 ;
     RECT  44.4 1.139 45.144 1.763 ;
     RECT  47.184 1.187 49.224 1.763 ;
     RECT  50.448 1.187 51.672 1.763 ;
     RECT  4.512 1.715 27.912 1.811 ;
     RECT  31.344 1.763 33.096 1.811 ;
     RECT  9.504 1.811 19.32 1.859 ;
     RECT  44.736 1.763 45.144 2.137 ;
     RECT  46.128 1.139 46.152 2.137 ;
     RECT  2.4 2.137 2.52 2.151 ;
     RECT  42.336 1.715 43.08 2.151 ;
     RECT  53.7 2.137 53.82 2.151 ;
     RECT  37.008 1.763 37.944 2.195 ;
     RECT  42.336 2.151 43.212 2.291 ;
     RECT  44.736 2.137 46.152 2.291 ;
     RECT  47.52 1.763 49.224 2.291 ;
     RECT  50.784 1.763 51.312 2.291 ;
     RECT  4.512 1.811 8.328 2.339 ;
     RECT  32.1 1.811 33.096 2.387 ;
     RECT  2.4 2.151 2.712 2.677 ;
     RECT  20.304 1.811 27.912 2.677 ;
     RECT  28.944 1.763 30.36 2.677 ;
     RECT  9.84 1.859 19.32 2.773 ;
     RECT  20.304 2.677 30.36 2.773 ;
     RECT  39.168 1.763 41.16 2.773 ;
     RECT  9.84 2.773 30.36 2.821 ;
     RECT  32.1 2.387 32.412 2.821 ;
     RECT  47.52 2.291 48.612 2.821 ;
     RECT  39.168 2.773 41.88 2.867 ;
     RECT  34.704 1.763 35.496 2.917 ;
     RECT  34.704 2.917 35.976 3.109 ;
     RECT  39.168 2.867 40.68 3.109 ;
     RECT  9.84 2.821 32.412 3.205 ;
     RECT  34.224 3.109 35.976 3.299 ;
     RECT  5.1 2.339 8.112 3.349 ;
     RECT  45.6 2.291 46.152 3.395 ;
     RECT  9.648 3.205 32.412 3.397 ;
     RECT  4.944 3.349 8.112 3.589 ;
     RECT  9.552 3.397 32.412 3.589 ;
     RECT  2.4 2.677 3.96 4.019 ;
     RECT  2.4 4.019 3.624 4.067 ;
     RECT  4.944 3.589 32.412 4.501 ;
     RECT  37.5 2.195 37.944 4.547 ;
     RECT  4.752 4.501 32.412 4.595 ;
     RECT  4.752 4.595 29.832 5.171 ;
     RECT  39.024 3.109 40.68 5.219 ;
     RECT  45.6 3.395 46.056 5.605 ;
     RECT  47.376 2.821 48.612 5.605 ;
     RECT  4.752 5.171 29.712 5.795 ;
     RECT  7.44 5.795 29.712 5.843 ;
     RECT  37.5 4.547 37.812 5.845 ;
     RECT  11.904 5.843 27.864 5.891 ;
     RECT  37.5 5.845 37.992 6.083 ;
     RECT  11.904 5.891 27.384 6.131 ;
     RECT  4.752 5.795 6.36 6.323 ;
     RECT  20.16 6.131 27.384 6.323 ;
     RECT  11.904 6.131 18.912 6.611 ;
     RECT  20.16 6.323 27.336 6.611 ;
     RECT  5.1 6.323 6.36 6.899 ;
     RECT  7.44 5.843 10.812 6.947 ;
     RECT  20.16 6.611 27.012 7.475 ;
     RECT  29.136 5.843 29.712 7.475 ;
     RECT  7.8 6.947 10.812 7.523 ;
     RECT  20.448 7.475 21.912 7.523 ;
     RECT  11.904 6.611 16.212 7.955 ;
     RECT  17.424 6.611 18.912 7.955 ;
     RECT  34.656 3.299 35.976 14.867 ;
     RECT  7.8 7.523 9.048 15.061 ;
     RECT  14.784 7.955 16.212 15.061 ;
     RECT  6.912 15.061 9.048 15.205 ;
     RECT  10.5 7.523 10.812 15.205 ;
     RECT  23.328 7.475 25.368 15.301 ;
     RECT  26.7 7.475 27.012 15.301 ;
     RECT  6.912 15.205 10.812 15.349 ;
     RECT  11.904 7.955 13.512 15.349 ;
     RECT  17.424 7.955 17.448 15.349 ;
     RECT  20.448 7.523 21.612 15.349 ;
     RECT  6.912 15.349 13.512 15.443 ;
     RECT  31.2 4.595 32.412 15.973 ;
     RECT  45.6 5.605 48.612 16.019 ;
     RECT  45.6 16.019 46.872 16.403 ;
     RECT  23.328 15.301 27.012 16.499 ;
     RECT  23.328 16.499 24.408 16.595 ;
     RECT  45.6 16.403 46.056 16.595 ;
     RECT  6.912 15.443 11.928 17.699 ;
     RECT  6.912 17.699 11.736 18.133 ;
     RECT  13.2 15.443 13.512 18.229 ;
     RECT  25.632 16.499 27.012 18.229 ;
     RECT  30.864 15.973 32.412 18.229 ;
     RECT  34.656 14.867 35.112 18.229 ;
     RECT  37.5 6.083 37.812 18.229 ;
     RECT  30.864 18.229 32.76 18.275 ;
     RECT  39.024 5.219 40.512 18.275 ;
     RECT  41.856 2.867 41.88 18.275 ;
     RECT  5.1 6.899 5.412 18.709 ;
     RECT  29.4 7.475 29.712 18.757 ;
     RECT  30.864 18.275 30.888 18.757 ;
     RECT  39.168 18.275 40.512 18.757 ;
     RECT  42.9 2.291 43.212 18.757 ;
     RECT  5.1 18.709 5.544 18.805 ;
     RECT  6.576 18.133 11.736 18.805 ;
     RECT  13.104 18.229 13.512 18.805 ;
     RECT  14.64 15.061 16.212 18.805 ;
     RECT  17.376 15.349 17.448 18.805 ;
     RECT  18.432 7.955 18.912 18.805 ;
     RECT  20.304 15.349 22.2 18.805 ;
     RECT  23.328 16.595 24.312 18.805 ;
     RECT  25.632 18.229 27.384 18.805 ;
     RECT  29.4 18.757 30.888 18.805 ;
     RECT  32.1 18.275 32.76 18.805 ;
     RECT  34.608 18.229 35.112 18.805 ;
     RECT  46.992 18.757 47.016 18.805 ;
     RECT  48.3 16.019 48.612 18.805 ;
     RECT  42.9 18.757 43.752 19.141 ;
     RECT  4.848 18.805 27.528 19.237 ;
     RECT  29.28 18.805 30.888 19.285 ;
     RECT  4.848 19.237 27.912 19.333 ;
     RECT  32.1 18.805 32.952 19.333 ;
     RECT  34.608 18.805 35.688 19.381 ;
     RECT  36.864 18.229 37.812 19.381 ;
     RECT  39.168 18.757 40.824 19.381 ;
     RECT  42.9 19.141 44.424 19.381 ;
     RECT  45.6 16.595 46.008 19.381 ;
     RECT  46.992 18.805 48.612 19.381 ;
     RECT  49.92 18.757 49.944 19.381 ;
     RECT  51 2.291 51.312 19.381 ;
     RECT  2.4 4.067 2.712 19.449 ;
     RECT  53.7 2.151 54.012 19.449 ;
     RECT  2.4 19.449 2.52 19.463 ;
     RECT  53.7 19.449 53.82 19.463 ;
     RECT  4.512 19.333 27.912 19.957 ;
     RECT  28.944 19.285 30.888 19.957 ;
     RECT  31.872 19.333 32.952 19.957 ;
     RECT  34.608 19.381 40.824 19.957 ;
     RECT  42 19.381 44.424 19.957 ;
     RECT  45.456 19.381 51.312 19.957 ;
     RECT  4.512 19.957 51.672 21.456 ;
  END
END hbfd_rly_136_SN_fc_f3
END LIBRARY
